VERSION 5.8 ;
BUSBITCHARS "[]" ;
DIVIDERCHAR "/" ;

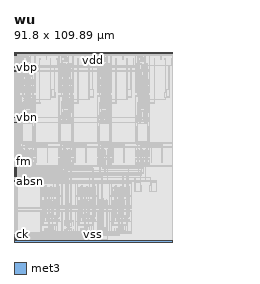
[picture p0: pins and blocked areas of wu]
MACRO wu
  CLASS BLOCK ;
  FOREIGN wu 0 0 ;
  ORIGIN 0 0 ;
  SIZE 91.800 BY 109.890 ;
  SYMMETRY X Y ;
  PIN absf
    DIRECTION OUTPUT ;
    USE SIGNAL ;
    PORT
      LAYER met3 ;
        RECT 0.000 41.260 1.400 41.600 ;
    END
  END absf
  PIN absn
    DIRECTION OUTPUT ;
    USE SIGNAL ;
    PORT
      LAYER met3 ;
        RECT 0.000 34.960 1.400 35.300 ;
    END
  END absn
  PIN ck
    DIRECTION INPUT ;
    USE SIGNAL ;
    PORT
      LAYER met3 ;
        RECT 0.000 3.930 1.400 4.270 ;
    END
  END ck
  PIN ck3
    DIRECTION INPUT ;
    USE SIGNAL ;
    PORT
      LAYER met3 ;
        RECT 0.000 3.230 1.400 3.570 ;
    END
  END ck3
  PIN fm
    DIRECTION INOUT ;
    USE SIGNAL ;
    PORT
      LAYER met3 ;
        RECT 0.000 41.960 1.400 42.300 ;
    END
  END fm
  PIN fp
    DIRECTION INOUT ;
    USE SIGNAL ;
    PORT
      LAYER met3 ;
        RECT 0.000 42.660 1.400 43.000 ;
    END
  END fp
  PIN lat
    DIRECTION INPUT ;
    USE SIGNAL ;
    PORT
      LAYER met3 ;
        RECT 0.000 2.530 1.400 2.870 ;
    END
  END lat
  PIN latb
    DIRECTION INPUT ;
    USE SIGNAL ;
    PORT
      LAYER met3 ;
        RECT 0.000 1.830 1.400 2.170 ;
    END
  END latb
  PIN lq
    DIRECTION INPUT ;
    USE SIGNAL ;
    PORT
      LAYER met3 ;
        RECT 0.000 1.130 1.400 1.470 ;
    END
  END lq
  PIN nm
    DIRECTION INOUT ;
    USE SIGNAL ;
    PORT
      LAYER met3 ;
        RECT 0.000 39.160 1.400 39.500 ;
    END
  END nm
  PIN np
    DIRECTION INOUT ;
    USE SIGNAL ;
    PORT
      LAYER met3 ;
        RECT 0.000 39.860 1.400 40.200 ;
    END
  END np
  PIN q1
    DIRECTION OUTPUT ;
    USE SIGNAL ;
    PORT
      LAYER met3 ;
        RECT 0.000 40.560 1.400 40.900 ;
    END
  END q1
  PIN q2
    DIRECTION OUTPUT ;
    USE SIGNAL ;
    PORT
      LAYER met3 ;
        RECT 0.000 38.460 1.400 38.800 ;
    END
  END q2
  PIN sen
    DIRECTION INPUT ;
    USE SIGNAL ;
    PORT
      LAYER met3 ;
        RECT 0.000 37.760 1.400 38.100 ;
    END
  END sen
  PIN vbn
    DIRECTION INPUT ;
    USE SIGNAL ;
    PORT
      LAYER met3 ;
        RECT 0.000 71.840 1.400 72.180 ;
    END
  END vbn
  PIN vbnc
    DIRECTION INPUT ;
    USE SIGNAL ;
    PORT
      LAYER met3 ;
        RECT 0.000 68.970 1.400 69.310 ;
    END
  END vbnc
  PIN vbp
    DIRECTION INPUT ;
    USE SIGNAL ;
    PORT
      LAYER met3 ;
        RECT 0.000 100.910 1.400 101.250 ;
    END
  END vbp
  PIN vbpc
    DIRECTION INPUT ;
    USE SIGNAL ;
    PORT
      LAYER met3 ;
        RECT 0.000 98.570 1.400 98.910 ;
    END
  END vbpc
  PIN vcm
    DIRECTION INOUT ;
    USE SIGNAL ;
    PORT
      LAYER met3 ;
        RECT 0.000 108.020 1.400 108.360 ;
    END
  END vcm
  PIN vdd
    DIRECTION INOUT ;
    USE POWER ;
    PORT
      LAYER met3 ;
        RECT 0.000 109.090 91.800 109.890 ;
    END
  END vdd
  PIN vss
    DIRECTION INOUT ;
    USE GROUND ;
    PORT
      LAYER met3 ;
        RECT 0.000 0.000 91.800 0.800 ;
    END
  END vss
  OBS
    LAYER li1 ;
      RECT 0.000 0.000 91.800 109.890 ;
    LAYER met1 ;
      RECT 40.800 6.920 41.030 9.690 ;
      RECT 37.415 9.690 45.960 10.030 ;
      RECT 45.960 6.920 46.190 10.030 ;
      RECT 45.810 10.210 46.150 10.550 ;
      RECT 46.045 12.230 46.275 14.400 ;
      RECT 46.045 14.400 46.745 14.740 ;
      RECT 41.155 12.230 41.385 15.340 ;
      RECT 41.385 15.000 47.345 15.340 ;
      RECT 15.350 5.350 15.690 5.790 ;
      RECT 27.410 5.350 28.090 5.790 ;
      RECT 35.840 5.350 36.520 5.790 ;
      RECT 48.240 5.350 48.920 5.790 ;
      RECT 55.440 5.350 56.120 5.790 ;
      RECT 29.270 6.130 29.500 7.220 ;
      RECT 31.850 6.130 32.080 7.220 ;
      RECT 34.430 6.130 34.660 7.220 ;
      RECT 17.740 6.130 17.970 7.920 ;
      RECT 38.570 6.130 38.800 7.920 ;
      RECT 53.325 6.130 53.555 7.920 ;
      RECT 58.170 6.130 58.400 7.920 ;
      RECT 15.350 6.130 15.690 11.700 ;
      RECT 35.840 6.130 36.520 11.700 ;
      RECT 55.440 6.130 56.120 11.700 ;
      RECT 21.115 12.040 21.345 13.230 ;
      RECT 22.845 12.040 23.075 13.230 ;
      RECT 24.425 12.040 24.655 13.230 ;
      RECT 26.005 12.040 26.235 13.230 ;
      RECT 41.945 12.040 42.175 13.230 ;
      RECT 43.675 12.040 43.905 13.230 ;
      RECT 45.255 12.040 45.485 13.230 ;
      RECT 46.835 12.040 47.065 13.230 ;
      RECT 61.545 12.040 61.775 13.230 ;
      RECT 63.275 12.040 63.505 13.230 ;
      RECT 64.855 12.040 65.085 13.230 ;
      RECT 66.435 12.040 66.665 13.230 ;
      RECT 15.350 12.040 15.690 17.670 ;
      RECT 27.410 6.130 28.090 17.670 ;
      RECT 15.350 11.700 27.410 12.040 ;
      RECT 35.840 12.040 36.520 17.670 ;
      RECT 48.240 6.130 48.920 17.670 ;
      RECT 35.840 11.700 48.240 12.040 ;
      RECT 55.440 12.040 56.120 17.670 ;
      RECT 55.440 11.700 67.840 12.040 ;
      RECT 0.300 17.670 67.840 18.170 ;
      RECT 67.840 5.350 68.180 18.170 ;
      RECT 0.300 4.850 68.180 5.350 ;
      RECT 15.350 5.790 67.840 6.130 ;
      RECT 44.315 21.090 44.545 24.460 ;
      RECT 45.255 21.090 45.485 24.460 ;
      RECT 39.215 24.460 46.835 24.800 ;
      RECT 46.835 21.090 47.065 24.800 ;
      RECT 44.785 27.000 45.015 29.170 ;
      RECT 44.785 29.170 46.365 29.510 ;
      RECT 46.365 27.000 46.595 29.510 ;
      RECT 43.995 27.000 44.225 29.770 ;
      RECT 43.995 29.770 47.155 30.110 ;
      RECT 47.155 27.000 47.385 30.110 ;
      RECT 37.375 27.000 37.605 31.310 ;
      RECT 37.605 30.970 47.345 31.310 ;
      RECT 15.350 20.120 15.690 20.560 ;
      RECT 27.410 20.120 28.090 20.560 ;
      RECT 35.840 20.120 36.520 20.560 ;
      RECT 48.240 20.120 48.920 20.560 ;
      RECT 55.440 20.120 56.120 20.560 ;
      RECT 20.175 20.900 20.405 22.090 ;
      RECT 22.695 20.900 22.925 22.090 ;
      RECT 31.850 20.900 32.080 22.090 ;
      RECT 41.005 20.900 41.235 22.090 ;
      RECT 43.525 20.900 43.755 22.090 ;
      RECT 60.605 20.900 60.835 22.090 ;
      RECT 63.125 20.900 63.355 22.090 ;
      RECT 17.655 20.900 17.885 23.090 ;
      RECT 25.215 20.900 25.445 23.090 ;
      RECT 38.485 20.900 38.715 23.090 ;
      RECT 46.045 20.900 46.275 23.090 ;
      RECT 58.085 20.900 58.315 23.090 ;
      RECT 65.645 20.900 65.875 23.090 ;
      RECT 53.325 20.900 53.555 23.690 ;
      RECT 15.350 20.900 15.690 26.470 ;
      RECT 35.840 20.900 36.520 26.470 ;
      RECT 55.440 20.900 56.120 26.470 ;
      RECT 17.335 26.810 17.565 29.000 ;
      RECT 20.645 26.810 20.875 29.000 ;
      RECT 24.745 26.810 24.975 29.000 ;
      RECT 38.165 26.810 38.395 29.000 ;
      RECT 41.475 26.810 41.705 29.000 ;
      RECT 45.575 26.810 45.805 29.000 ;
      RECT 57.765 26.810 57.995 29.000 ;
      RECT 61.075 26.810 61.305 29.000 ;
      RECT 65.175 26.810 65.405 29.000 ;
      RECT 15.350 26.810 15.690 33.690 ;
      RECT 27.410 20.900 28.090 33.690 ;
      RECT 15.350 26.470 27.410 26.810 ;
      RECT 35.840 26.810 36.520 33.690 ;
      RECT 48.240 20.900 48.920 33.690 ;
      RECT 35.840 26.470 48.240 26.810 ;
      RECT 55.440 26.810 56.120 33.690 ;
      RECT 1.500 33.690 67.840 34.190 ;
      RECT 67.840 20.120 68.180 34.190 ;
      RECT 1.500 19.620 68.180 20.120 ;
      RECT 15.350 20.560 67.840 20.900 ;
      RECT 55.440 26.470 67.840 26.810 ;
      RECT 3.810 44.080 4.150 47.640 ;
      RECT 25.910 44.080 26.250 47.640 ;
      RECT 48.010 44.080 48.350 47.640 ;
      RECT 70.110 44.080 70.450 47.640 ;
      RECT 3.810 47.640 11.900 48.140 ;
      RECT 11.900 44.080 12.240 48.140 ;
      RECT 25.910 47.640 34.000 48.140 ;
      RECT 34.000 44.080 34.340 48.140 ;
      RECT 48.010 47.640 56.100 48.140 ;
      RECT 56.100 44.080 56.440 48.140 ;
      RECT 70.110 47.640 78.200 48.140 ;
      RECT 78.200 44.080 78.540 48.140 ;
      RECT 0.300 43.580 91.800 44.080 ;
      RECT 3.810 50.090 4.150 54.650 ;
      RECT 11.900 49.590 12.240 54.650 ;
      RECT 3.810 49.590 11.900 50.090 ;
      RECT 25.910 50.090 26.250 54.650 ;
      RECT 34.000 49.590 34.340 54.650 ;
      RECT 25.910 49.590 34.000 50.090 ;
      RECT 48.010 50.090 48.350 54.650 ;
      RECT 56.100 49.590 56.440 54.650 ;
      RECT 48.010 49.590 56.100 50.090 ;
      RECT 70.110 50.090 70.450 54.650 ;
      RECT 1.500 54.650 91.800 55.150 ;
      RECT 78.200 50.090 78.540 54.650 ;
      RECT 70.110 49.590 78.540 50.090 ;
      RECT 3.810 57.530 4.150 59.940 ;
      RECT 25.910 57.530 26.250 59.940 ;
      RECT 48.010 57.530 48.350 59.940 ;
      RECT 70.110 57.530 70.450 59.940 ;
      RECT 5.540 60.280 5.770 61.220 ;
      RECT 6.330 60.280 6.560 61.220 ;
      RECT 7.910 60.280 8.140 61.220 ;
      RECT 9.490 60.280 9.720 61.220 ;
      RECT 10.280 60.280 10.510 61.220 ;
      RECT 27.640 60.280 27.870 61.220 ;
      RECT 28.430 60.280 28.660 61.220 ;
      RECT 30.010 60.280 30.240 61.220 ;
      RECT 31.590 60.280 31.820 61.220 ;
      RECT 32.380 60.280 32.610 61.220 ;
      RECT 49.740 60.280 49.970 61.220 ;
      RECT 50.530 60.280 50.760 61.220 ;
      RECT 52.110 60.280 52.340 61.220 ;
      RECT 53.690 60.280 53.920 61.220 ;
      RECT 54.480 60.280 54.710 61.220 ;
      RECT 71.840 60.280 72.070 61.220 ;
      RECT 72.630 60.280 72.860 61.220 ;
      RECT 74.210 60.280 74.440 61.220 ;
      RECT 75.790 60.280 76.020 61.220 ;
      RECT 76.580 60.280 76.810 61.220 ;
      RECT 3.810 60.280 4.150 62.750 ;
      RECT 25.910 60.280 26.250 62.750 ;
      RECT 48.010 60.280 48.350 62.750 ;
      RECT 70.110 60.280 70.450 62.750 ;
      RECT 5.540 63.090 5.770 64.030 ;
      RECT 6.330 63.090 6.560 64.030 ;
      RECT 7.910 63.090 8.140 64.030 ;
      RECT 9.490 63.090 9.720 64.030 ;
      RECT 10.280 63.090 10.510 64.030 ;
      RECT 27.640 63.090 27.870 64.030 ;
      RECT 28.430 63.090 28.660 64.030 ;
      RECT 30.010 63.090 30.240 64.030 ;
      RECT 31.590 63.090 31.820 64.030 ;
      RECT 32.380 63.090 32.610 64.030 ;
      RECT 49.740 63.090 49.970 64.030 ;
      RECT 50.530 63.090 50.760 64.030 ;
      RECT 52.110 63.090 52.340 64.030 ;
      RECT 53.690 63.090 53.920 64.030 ;
      RECT 54.480 63.090 54.710 64.030 ;
      RECT 71.840 63.090 72.070 64.030 ;
      RECT 72.630 63.090 72.860 64.030 ;
      RECT 74.210 63.090 74.440 64.030 ;
      RECT 75.790 63.090 76.020 64.030 ;
      RECT 76.580 63.090 76.810 64.030 ;
      RECT 3.810 63.090 4.150 69.720 ;
      RECT 25.910 63.090 26.250 69.720 ;
      RECT 48.010 63.090 48.350 69.720 ;
      RECT 70.110 63.090 70.450 69.720 ;
      RECT 4.685 70.060 4.915 71.150 ;
      RECT 7.265 70.060 7.495 71.150 ;
      RECT 9.845 70.060 10.075 71.150 ;
      RECT 26.785 70.060 27.015 71.150 ;
      RECT 29.365 70.060 29.595 71.150 ;
      RECT 31.945 70.060 32.175 71.150 ;
      RECT 48.885 70.060 49.115 71.150 ;
      RECT 51.465 70.060 51.695 71.150 ;
      RECT 54.045 70.060 54.275 71.150 ;
      RECT 70.985 70.060 71.215 71.150 ;
      RECT 73.565 70.060 73.795 71.150 ;
      RECT 76.145 70.060 76.375 71.150 ;
      RECT 5.860 73.020 6.090 74.710 ;
      RECT 3.810 70.060 4.150 73.020 ;
      RECT 7.440 72.680 7.670 74.710 ;
      RECT 4.150 72.680 7.440 73.020 ;
      RECT 27.960 73.020 28.190 74.710 ;
      RECT 25.910 70.060 26.250 73.020 ;
      RECT 29.540 72.680 29.770 74.710 ;
      RECT 26.250 72.680 29.540 73.020 ;
      RECT 50.060 73.020 50.290 74.710 ;
      RECT 48.010 70.060 48.350 73.020 ;
      RECT 51.640 72.680 51.870 74.710 ;
      RECT 48.350 72.680 51.640 73.020 ;
      RECT 72.160 73.020 72.390 74.710 ;
      RECT 70.110 70.060 70.450 73.020 ;
      RECT 73.740 72.680 73.970 74.710 ;
      RECT 70.450 72.680 73.740 73.020 ;
      RECT 3.810 73.020 4.150 84.240 ;
      RECT 25.910 73.020 26.250 84.240 ;
      RECT 48.010 73.020 48.350 84.240 ;
      RECT 70.110 73.020 70.450 84.240 ;
      RECT 3.810 59.940 11.900 60.280 ;
      RECT 3.810 62.750 11.900 63.090 ;
      RECT 3.810 84.240 12.240 84.740 ;
      RECT 11.900 57.530 12.240 84.240 ;
      RECT 3.810 69.720 11.900 70.060 ;
      RECT 25.910 59.940 34.000 60.280 ;
      RECT 25.910 62.750 34.000 63.090 ;
      RECT 25.910 84.240 34.340 84.740 ;
      RECT 34.000 57.530 34.340 84.240 ;
      RECT 25.910 69.720 34.000 70.060 ;
      RECT 48.010 59.940 56.100 60.280 ;
      RECT 48.010 62.750 56.100 63.090 ;
      RECT 48.010 84.240 56.440 84.740 ;
      RECT 56.100 57.530 56.440 84.240 ;
      RECT 48.010 69.720 56.100 70.060 ;
      RECT 70.110 84.240 78.540 84.740 ;
      RECT 78.200 57.530 78.540 84.240 ;
      RECT 0.300 57.030 91.800 57.530 ;
      RECT 70.110 59.940 78.200 60.280 ;
      RECT 70.110 62.750 78.200 63.090 ;
      RECT 70.110 69.720 78.200 70.060 ;
      RECT 3.810 86.690 4.150 87.130 ;
      RECT 25.910 86.690 26.250 87.130 ;
      RECT 48.010 86.690 48.350 87.130 ;
      RECT 70.110 86.690 70.450 87.130 ;
      RECT 4.640 87.470 4.870 89.660 ;
      RECT 5.730 87.470 5.960 89.660 ;
      RECT 7.910 87.470 8.140 89.660 ;
      RECT 10.090 87.470 10.320 89.660 ;
      RECT 11.180 87.470 11.410 89.660 ;
      RECT 26.740 87.470 26.970 89.660 ;
      RECT 27.830 87.470 28.060 89.660 ;
      RECT 30.010 87.470 30.240 89.660 ;
      RECT 32.190 87.470 32.420 89.660 ;
      RECT 33.280 87.470 33.510 89.660 ;
      RECT 48.840 87.470 49.070 89.660 ;
      RECT 49.930 87.470 50.160 89.660 ;
      RECT 52.110 87.470 52.340 89.660 ;
      RECT 54.290 87.470 54.520 89.660 ;
      RECT 55.380 87.470 55.610 89.660 ;
      RECT 70.940 87.470 71.170 89.660 ;
      RECT 72.030 87.470 72.260 89.660 ;
      RECT 74.210 87.470 74.440 89.660 ;
      RECT 76.390 87.470 76.620 89.660 ;
      RECT 77.480 87.470 77.710 89.660 ;
      RECT 3.810 87.470 4.150 91.190 ;
      RECT 25.910 87.470 26.250 91.190 ;
      RECT 48.010 87.470 48.350 91.190 ;
      RECT 70.110 87.470 70.450 91.190 ;
      RECT 4.640 91.530 4.870 93.720 ;
      RECT 5.730 91.530 5.960 93.720 ;
      RECT 7.910 91.530 8.140 93.720 ;
      RECT 10.090 91.530 10.320 93.720 ;
      RECT 11.180 91.530 11.410 93.720 ;
      RECT 26.740 91.530 26.970 93.720 ;
      RECT 27.830 91.530 28.060 93.720 ;
      RECT 30.010 91.530 30.240 93.720 ;
      RECT 32.190 91.530 32.420 93.720 ;
      RECT 33.280 91.530 33.510 93.720 ;
      RECT 48.840 91.530 49.070 93.720 ;
      RECT 49.930 91.530 50.160 93.720 ;
      RECT 52.110 91.530 52.340 93.720 ;
      RECT 54.290 91.530 54.520 93.720 ;
      RECT 55.380 91.530 55.610 93.720 ;
      RECT 70.940 91.530 71.170 93.720 ;
      RECT 72.030 91.530 72.260 93.720 ;
      RECT 74.210 91.530 74.440 93.720 ;
      RECT 76.390 91.530 76.620 93.720 ;
      RECT 77.480 91.530 77.710 93.720 ;
      RECT 3.810 91.530 4.150 99.410 ;
      RECT 25.910 91.530 26.250 99.410 ;
      RECT 48.010 91.530 48.350 99.410 ;
      RECT 70.110 91.530 70.450 99.410 ;
      RECT 6.105 99.750 6.335 101.940 ;
      RECT 28.205 99.750 28.435 101.940 ;
      RECT 50.305 99.750 50.535 101.940 ;
      RECT 72.405 99.750 72.635 101.940 ;
      RECT 8.135 99.750 8.365 102.440 ;
      RECT 9.715 99.750 9.945 102.440 ;
      RECT 30.235 99.750 30.465 102.440 ;
      RECT 31.815 99.750 32.045 102.440 ;
      RECT 52.335 99.750 52.565 102.440 ;
      RECT 53.915 99.750 54.145 102.440 ;
      RECT 74.435 99.750 74.665 102.440 ;
      RECT 76.015 99.750 76.245 102.440 ;
      RECT 3.810 99.750 4.150 108.150 ;
      RECT 3.810 99.410 11.900 99.750 ;
      RECT 3.810 87.130 11.900 87.470 ;
      RECT 3.810 91.190 11.900 91.530 ;
      RECT 11.900 86.690 12.240 108.150 ;
      RECT 3.810 86.190 12.240 86.690 ;
      RECT 25.910 99.750 26.250 108.150 ;
      RECT 25.910 99.410 34.000 99.750 ;
      RECT 25.910 87.130 34.000 87.470 ;
      RECT 25.910 91.190 34.000 91.530 ;
      RECT 34.000 86.690 34.340 108.150 ;
      RECT 25.910 86.190 34.340 86.690 ;
      RECT 48.010 99.750 48.350 108.150 ;
      RECT 48.010 99.410 56.100 99.750 ;
      RECT 48.010 87.130 56.100 87.470 ;
      RECT 48.010 91.190 56.100 91.530 ;
      RECT 56.100 86.690 56.440 108.150 ;
      RECT 48.010 86.190 56.440 86.690 ;
      RECT 70.110 99.750 70.450 108.150 ;
      RECT 70.110 99.410 78.200 99.750 ;
      RECT 1.500 108.150 91.800 108.650 ;
      RECT 78.200 86.690 78.540 108.150 ;
      RECT 70.110 86.190 78.540 86.690 ;
      RECT 70.110 87.130 78.200 87.470 ;
      RECT 70.110 91.190 78.200 91.530 ;
      RECT 76.255 82.780 76.595 83.120 ;
      RECT 72.055 83.340 72.395 83.680 ;
      RECT 73.120 87.660 73.350 89.830 ;
      RECT 73.120 89.830 74.190 90.170 ;
      RECT 74.460 89.830 75.530 90.170 ;
      RECT 75.300 87.660 75.530 89.830 ;
      RECT 70.855 90.350 71.195 90.690 ;
      RECT 73.120 91.720 73.350 93.890 ;
      RECT 73.120 93.890 74.790 94.230 ;
      RECT 73.860 94.490 75.530 94.830 ;
      RECT 75.300 91.720 75.530 94.490 ;
      RECT 70.855 95.010 71.195 95.350 ;
      RECT 72.160 96.190 72.390 97.880 ;
      RECT 73.740 96.190 73.970 97.880 ;
      RECT 72.160 95.850 74.190 96.190 ;
      RECT 74.680 96.190 74.910 97.880 ;
      RECT 76.260 95.850 76.490 97.880 ;
      RECT 74.460 95.850 76.260 96.190 ;
      RECT 72.660 98.050 73.180 98.390 ;
      RECT 72.950 96.380 73.180 98.050 ;
      RECT 75.470 96.380 75.700 98.050 ;
      RECT 75.470 98.050 75.990 98.390 ;
      RECT 77.455 98.570 77.795 98.910 ;
      RECT 72.060 102.610 73.725 102.950 ;
      RECT 73.495 99.940 73.725 102.610 ;
      RECT 75.225 99.940 75.455 102.610 ;
      RECT 75.225 102.610 77.190 102.950 ;
      RECT 70.855 103.130 71.195 103.470 ;
      RECT 72.055 103.690 72.395 104.030 ;
      RECT 69.055 105.345 69.395 105.995 ;
      RECT 81.005 105.345 81.345 105.995 ;
      RECT 84.855 105.345 85.195 105.995 ;
      RECT 87.305 105.345 87.645 105.995 ;
      RECT 91.155 105.345 91.495 105.995 ;
      RECT 73.420 104.870 73.650 106.560 ;
      RECT 75.000 104.530 75.230 106.560 ;
      RECT 72.060 104.530 75.000 104.870 ;
      RECT 71.460 106.730 74.210 107.070 ;
      RECT 74.210 105.060 74.440 107.070 ;
      RECT 75.655 107.250 75.995 107.590 ;
      RECT 51.760 94.490 53.430 94.830 ;
      RECT 53.200 91.720 53.430 94.490 ;
      RECT 49.960 102.610 51.625 102.950 ;
      RECT 51.395 99.940 51.625 102.610 ;
      RECT 53.125 99.940 53.355 102.610 ;
      RECT 53.125 102.610 55.090 102.950 ;
      RECT 49.955 83.340 50.295 83.680 ;
      RECT 48.755 95.010 49.095 95.350 ;
      RECT 48.755 103.130 49.095 103.470 ;
      RECT 54.155 82.780 54.495 83.120 ;
      RECT 49.955 103.690 50.295 104.030 ;
      RECT 50.060 96.190 50.290 97.880 ;
      RECT 51.640 96.190 51.870 97.880 ;
      RECT 50.060 95.850 52.090 96.190 ;
      RECT 46.955 105.345 47.295 105.995 ;
      RECT 58.905 105.345 59.245 105.995 ;
      RECT 62.755 105.345 63.095 105.995 ;
      RECT 65.205 105.345 65.545 105.995 ;
      RECT 52.580 96.190 52.810 97.880 ;
      RECT 54.160 95.850 54.390 97.880 ;
      RECT 52.360 95.850 54.160 96.190 ;
      RECT 48.755 90.350 49.095 90.690 ;
      RECT 51.020 87.660 51.250 89.830 ;
      RECT 51.020 89.830 52.090 90.170 ;
      RECT 50.560 98.050 51.080 98.390 ;
      RECT 50.850 96.380 51.080 98.050 ;
      RECT 53.370 96.380 53.600 98.050 ;
      RECT 53.370 98.050 53.890 98.390 ;
      RECT 51.320 104.870 51.550 106.560 ;
      RECT 52.900 104.530 53.130 106.560 ;
      RECT 49.960 104.530 52.900 104.870 ;
      RECT 51.020 91.720 51.250 93.890 ;
      RECT 51.020 93.890 52.690 94.230 ;
      RECT 49.360 106.730 52.110 107.070 ;
      RECT 52.110 105.060 52.340 107.070 ;
      RECT 52.360 89.830 53.430 90.170 ;
      RECT 53.200 87.660 53.430 89.830 ;
      RECT 53.555 107.250 53.895 107.590 ;
      RECT 55.355 98.570 55.695 98.910 ;
      RECT 52.360 78.850 53.130 79.190 ;
      RECT 52.900 77.930 53.130 78.850 ;
      RECT 49.955 79.370 50.295 79.710 ;
      RECT 54.155 79.370 54.495 79.710 ;
      RECT 49.740 80.550 49.970 81.490 ;
      RECT 50.530 80.550 50.760 81.490 ;
      RECT 52.110 80.550 52.340 81.490 ;
      RECT 53.690 80.550 53.920 81.490 ;
      RECT 54.480 80.210 54.710 81.490 ;
      RECT 49.360 80.210 54.480 80.550 ;
      RECT 51.320 80.740 51.550 82.000 ;
      RECT 51.550 81.660 52.690 82.000 ;
      RECT 51.760 82.260 52.900 82.600 ;
      RECT 52.900 80.740 53.130 82.600 ;
      RECT 51.320 60.470 51.550 61.390 ;
      RECT 51.320 61.390 52.090 61.730 ;
      RECT 52.360 61.390 53.130 61.730 ;
      RECT 52.900 60.470 53.130 61.390 ;
      RECT 50.555 61.910 50.895 62.250 ;
      RECT 51.320 63.280 51.550 64.540 ;
      RECT 51.550 64.200 52.690 64.540 ;
      RECT 49.360 58.545 51.835 58.885 ;
      RECT 51.760 64.800 52.900 65.140 ;
      RECT 52.900 63.280 53.130 65.140 ;
      RECT 50.555 65.320 50.895 65.660 ;
      RECT 50.060 66.500 50.290 68.190 ;
      RECT 51.640 66.500 51.870 68.190 ;
      RECT 50.060 66.160 52.090 66.500 ;
      RECT 52.580 66.500 52.810 68.190 ;
      RECT 54.160 66.160 54.390 68.190 ;
      RECT 52.360 66.160 54.160 66.500 ;
      RECT 50.560 68.360 51.080 68.700 ;
      RECT 50.850 66.690 51.080 68.360 ;
      RECT 53.370 66.690 53.600 68.360 ;
      RECT 53.370 68.360 53.890 68.700 ;
      RECT 48.755 68.880 49.095 69.220 ;
      RECT 50.175 70.250 50.405 71.320 ;
      RECT 49.360 71.320 52.755 71.660 ;
      RECT 52.755 70.250 52.985 71.660 ;
      RECT 54.160 71.320 55.335 71.660 ;
      RECT 55.335 70.250 55.565 71.660 ;
      RECT 55.355 71.840 55.695 72.180 ;
      RECT 52.580 73.020 52.810 74.710 ;
      RECT 54.160 73.020 54.390 74.710 ;
      RECT 52.580 72.680 54.490 73.020 ;
      RECT 53.370 73.210 53.600 75.220 ;
      RECT 53.600 74.880 55.690 75.220 ;
      RECT 50.850 73.210 51.080 75.820 ;
      RECT 51.080 75.480 55.090 75.820 ;
      RECT 54.155 76.000 54.495 76.340 ;
      RECT 53.555 76.560 53.895 76.900 ;
      RECT 49.740 77.740 49.970 78.680 ;
      RECT 50.530 77.740 50.760 78.680 ;
      RECT 52.110 77.740 52.340 78.680 ;
      RECT 53.690 77.740 53.920 78.680 ;
      RECT 54.480 77.400 54.710 78.680 ;
      RECT 49.360 77.400 54.480 77.740 ;
      RECT 51.320 77.930 51.550 78.850 ;
      RECT 51.320 78.850 52.090 79.190 ;
      RECT 52.615 58.545 55.090 58.885 ;
      RECT 76.255 79.370 76.595 79.710 ;
      RECT 73.860 64.800 75.000 65.140 ;
      RECT 75.000 63.280 75.230 65.140 ;
      RECT 71.840 80.550 72.070 81.490 ;
      RECT 72.630 80.550 72.860 81.490 ;
      RECT 74.210 80.550 74.440 81.490 ;
      RECT 75.790 80.550 76.020 81.490 ;
      RECT 76.580 80.210 76.810 81.490 ;
      RECT 71.460 80.210 76.580 80.550 ;
      RECT 74.460 61.390 75.230 61.730 ;
      RECT 75.000 60.470 75.230 61.390 ;
      RECT 73.420 80.740 73.650 82.000 ;
      RECT 73.650 81.660 74.790 82.000 ;
      RECT 72.275 70.250 72.505 71.320 ;
      RECT 71.460 71.320 74.855 71.660 ;
      RECT 74.855 70.250 75.085 71.660 ;
      RECT 73.860 82.260 75.000 82.600 ;
      RECT 75.000 80.740 75.230 82.600 ;
      RECT 76.260 71.320 77.435 71.660 ;
      RECT 77.435 70.250 77.665 71.660 ;
      RECT 72.655 65.320 72.995 65.660 ;
      RECT 77.455 71.840 77.795 72.180 ;
      RECT 71.460 58.545 73.935 58.885 ;
      RECT 74.680 73.020 74.910 74.710 ;
      RECT 76.260 73.020 76.490 74.710 ;
      RECT 74.680 72.680 76.590 73.020 ;
      RECT 72.655 61.910 72.995 62.250 ;
      RECT 75.470 73.210 75.700 75.220 ;
      RECT 75.700 74.880 77.790 75.220 ;
      RECT 72.160 66.500 72.390 68.190 ;
      RECT 73.740 66.500 73.970 68.190 ;
      RECT 72.160 66.160 74.190 66.500 ;
      RECT 72.950 73.210 73.180 75.820 ;
      RECT 73.180 75.480 77.190 75.820 ;
      RECT 74.680 66.500 74.910 68.190 ;
      RECT 76.260 66.160 76.490 68.190 ;
      RECT 74.460 66.160 76.260 66.500 ;
      RECT 76.255 76.000 76.595 76.340 ;
      RECT 74.715 58.545 77.190 58.885 ;
      RECT 75.655 76.560 75.995 76.900 ;
      RECT 73.420 63.280 73.650 64.540 ;
      RECT 73.650 64.200 74.790 64.540 ;
      RECT 71.840 77.740 72.070 78.680 ;
      RECT 72.630 77.740 72.860 78.680 ;
      RECT 74.210 77.740 74.440 78.680 ;
      RECT 75.790 77.740 76.020 78.680 ;
      RECT 76.580 77.400 76.810 78.680 ;
      RECT 71.460 77.400 76.580 77.740 ;
      RECT 72.660 68.360 73.180 68.700 ;
      RECT 72.950 66.690 73.180 68.360 ;
      RECT 75.470 66.690 75.700 68.360 ;
      RECT 75.470 68.360 75.990 68.700 ;
      RECT 73.420 77.930 73.650 78.850 ;
      RECT 73.420 78.850 74.190 79.190 ;
      RECT 74.460 78.850 75.230 79.190 ;
      RECT 75.000 77.930 75.230 78.850 ;
      RECT 73.420 60.470 73.650 61.390 ;
      RECT 73.420 61.390 74.190 61.730 ;
      RECT 70.855 68.880 71.195 69.220 ;
      RECT 72.055 79.370 72.395 79.710 ;
      RECT 32.055 82.780 32.395 83.120 ;
      RECT 27.855 83.340 28.195 83.680 ;
      RECT 28.920 87.660 29.150 89.830 ;
      RECT 28.920 89.830 29.990 90.170 ;
      RECT 30.260 89.830 31.330 90.170 ;
      RECT 31.100 87.660 31.330 89.830 ;
      RECT 26.655 90.350 26.995 90.690 ;
      RECT 28.920 91.720 29.150 93.890 ;
      RECT 28.920 93.890 30.590 94.230 ;
      RECT 29.660 94.490 31.330 94.830 ;
      RECT 31.100 91.720 31.330 94.490 ;
      RECT 26.655 95.010 26.995 95.350 ;
      RECT 27.960 96.190 28.190 97.880 ;
      RECT 29.540 96.190 29.770 97.880 ;
      RECT 27.960 95.850 29.990 96.190 ;
      RECT 30.480 96.190 30.710 97.880 ;
      RECT 32.060 95.850 32.290 97.880 ;
      RECT 30.260 95.850 32.060 96.190 ;
      RECT 28.460 98.050 28.980 98.390 ;
      RECT 28.750 96.380 28.980 98.050 ;
      RECT 31.270 96.380 31.500 98.050 ;
      RECT 31.270 98.050 31.790 98.390 ;
      RECT 33.255 98.570 33.595 98.910 ;
      RECT 27.860 102.610 29.525 102.950 ;
      RECT 29.295 99.940 29.525 102.610 ;
      RECT 31.025 99.940 31.255 102.610 ;
      RECT 31.025 102.610 32.990 102.950 ;
      RECT 26.655 103.130 26.995 103.470 ;
      RECT 27.855 103.690 28.195 104.030 ;
      RECT 24.855 105.345 25.195 105.995 ;
      RECT 36.805 105.345 37.145 105.995 ;
      RECT 40.655 105.345 40.995 105.995 ;
      RECT 43.105 105.345 43.445 105.995 ;
      RECT 29.220 104.870 29.450 106.560 ;
      RECT 30.800 104.530 31.030 106.560 ;
      RECT 27.860 104.530 30.800 104.870 ;
      RECT 27.260 106.730 30.010 107.070 ;
      RECT 30.010 105.060 30.240 107.070 ;
      RECT 31.455 107.250 31.795 107.590 ;
      RECT 11.155 98.570 11.495 98.910 ;
      RECT 7.560 94.490 9.230 94.830 ;
      RECT 9.000 91.720 9.230 94.490 ;
      RECT 5.760 102.610 7.425 102.950 ;
      RECT 7.195 99.940 7.425 102.610 ;
      RECT 8.925 99.940 9.155 102.610 ;
      RECT 8.925 102.610 10.890 102.950 ;
      RECT 5.755 83.340 6.095 83.680 ;
      RECT 4.555 95.010 4.895 95.350 ;
      RECT 4.555 103.130 4.895 103.470 ;
      RECT 9.955 82.780 10.295 83.120 ;
      RECT 5.755 103.690 6.095 104.030 ;
      RECT 5.860 96.190 6.090 97.880 ;
      RECT 7.440 96.190 7.670 97.880 ;
      RECT 5.860 95.850 7.890 96.190 ;
      RECT 14.705 105.345 15.045 105.995 ;
      RECT 18.555 105.345 18.895 105.995 ;
      RECT 21.005 105.345 21.345 105.995 ;
      RECT 8.380 96.190 8.610 97.880 ;
      RECT 9.960 95.850 10.190 97.880 ;
      RECT 8.160 95.850 9.960 96.190 ;
      RECT 4.555 90.350 4.895 90.690 ;
      RECT 6.820 87.660 7.050 89.830 ;
      RECT 6.820 89.830 7.890 90.170 ;
      RECT 6.360 98.050 6.880 98.390 ;
      RECT 6.650 96.380 6.880 98.050 ;
      RECT 7.120 104.870 7.350 106.560 ;
      RECT 8.700 104.530 8.930 106.560 ;
      RECT 5.760 104.530 8.700 104.870 ;
      RECT 9.170 96.380 9.400 98.050 ;
      RECT 9.170 98.050 9.690 98.390 ;
      RECT 5.160 106.730 7.910 107.070 ;
      RECT 7.910 105.060 8.140 107.070 ;
      RECT 6.820 91.720 7.050 93.890 ;
      RECT 6.820 93.890 8.490 94.230 ;
      RECT 9.355 107.250 9.695 107.590 ;
      RECT 8.160 89.830 9.230 90.170 ;
      RECT 9.000 87.660 9.230 89.830 ;
      RECT 9.170 73.210 9.400 75.220 ;
      RECT 9.400 74.880 11.490 75.220 ;
      RECT 7.120 77.930 7.350 78.850 ;
      RECT 7.120 78.850 7.890 79.190 ;
      RECT 6.355 65.320 6.695 65.660 ;
      RECT 9.955 76.000 10.295 76.340 ;
      RECT 8.160 78.850 8.930 79.190 ;
      RECT 8.700 77.930 8.930 78.850 ;
      RECT 7.120 60.470 7.350 61.390 ;
      RECT 7.120 61.390 7.890 61.730 ;
      RECT 8.415 58.545 10.890 58.885 ;
      RECT 7.120 63.280 7.350 64.540 ;
      RECT 7.350 64.200 8.490 64.540 ;
      RECT 7.560 82.260 8.700 82.600 ;
      RECT 8.700 80.740 8.930 82.600 ;
      RECT 8.380 73.020 8.610 74.710 ;
      RECT 9.960 73.020 10.190 74.710 ;
      RECT 8.380 72.680 10.290 73.020 ;
      RECT 6.650 73.210 6.880 75.820 ;
      RECT 6.880 75.480 10.890 75.820 ;
      RECT 8.160 61.390 8.930 61.730 ;
      RECT 8.700 60.470 8.930 61.390 ;
      RECT 9.355 76.560 9.695 76.900 ;
      RECT 6.360 68.360 6.880 68.700 ;
      RECT 6.650 66.690 6.880 68.360 ;
      RECT 5.860 66.500 6.090 68.190 ;
      RECT 7.440 66.500 7.670 68.190 ;
      RECT 5.860 66.160 7.890 66.500 ;
      RECT 5.755 79.370 6.095 79.710 ;
      RECT 9.955 79.370 10.295 79.710 ;
      RECT 4.555 68.880 4.895 69.220 ;
      RECT 11.155 71.840 11.495 72.180 ;
      RECT 9.170 66.690 9.400 68.360 ;
      RECT 9.170 68.360 9.690 68.700 ;
      RECT 7.560 64.800 8.700 65.140 ;
      RECT 8.700 63.280 8.930 65.140 ;
      RECT 5.540 77.740 5.770 78.680 ;
      RECT 6.330 77.740 6.560 78.680 ;
      RECT 7.910 77.740 8.140 78.680 ;
      RECT 9.490 77.740 9.720 78.680 ;
      RECT 10.280 77.400 10.510 78.680 ;
      RECT 5.160 77.400 10.280 77.740 ;
      RECT 6.355 61.910 6.695 62.250 ;
      RECT 5.540 80.550 5.770 81.490 ;
      RECT 6.330 80.550 6.560 81.490 ;
      RECT 7.910 80.550 8.140 81.490 ;
      RECT 9.490 80.550 9.720 81.490 ;
      RECT 10.280 80.210 10.510 81.490 ;
      RECT 5.160 80.210 10.280 80.550 ;
      RECT 5.160 58.545 7.635 58.885 ;
      RECT 8.380 66.500 8.610 68.190 ;
      RECT 9.960 66.160 10.190 68.190 ;
      RECT 8.160 66.160 9.960 66.500 ;
      RECT 5.975 70.250 6.205 71.320 ;
      RECT 5.160 71.320 8.555 71.660 ;
      RECT 8.555 70.250 8.785 71.660 ;
      RECT 9.960 71.320 11.135 71.660 ;
      RECT 11.135 70.250 11.365 71.660 ;
      RECT 7.120 80.740 7.350 82.000 ;
      RECT 7.350 81.660 8.490 82.000 ;
      RECT 28.455 65.320 28.795 65.660 ;
      RECT 32.060 71.320 33.235 71.660 ;
      RECT 33.235 70.250 33.465 71.660 ;
      RECT 29.220 80.740 29.450 82.000 ;
      RECT 29.450 81.660 30.590 82.000 ;
      RECT 30.515 58.545 32.990 58.885 ;
      RECT 31.270 73.210 31.500 75.220 ;
      RECT 31.500 74.880 33.590 75.220 ;
      RECT 28.455 61.910 28.795 62.250 ;
      RECT 27.960 66.500 28.190 68.190 ;
      RECT 29.540 66.500 29.770 68.190 ;
      RECT 27.960 66.160 29.990 66.500 ;
      RECT 29.220 63.280 29.450 64.540 ;
      RECT 29.450 64.200 30.590 64.540 ;
      RECT 29.220 60.470 29.450 61.390 ;
      RECT 29.220 61.390 29.990 61.730 ;
      RECT 30.260 61.390 31.030 61.730 ;
      RECT 30.800 60.470 31.030 61.390 ;
      RECT 32.055 76.000 32.395 76.340 ;
      RECT 29.660 82.260 30.800 82.600 ;
      RECT 30.800 80.740 31.030 82.600 ;
      RECT 27.855 79.370 28.195 79.710 ;
      RECT 32.055 79.370 32.395 79.710 ;
      RECT 27.640 77.740 27.870 78.680 ;
      RECT 28.430 77.740 28.660 78.680 ;
      RECT 30.010 77.740 30.240 78.680 ;
      RECT 31.590 77.740 31.820 78.680 ;
      RECT 32.380 77.400 32.610 78.680 ;
      RECT 27.260 77.400 32.380 77.740 ;
      RECT 26.655 68.880 26.995 69.220 ;
      RECT 28.460 68.360 28.980 68.700 ;
      RECT 28.750 66.690 28.980 68.360 ;
      RECT 31.270 66.690 31.500 68.360 ;
      RECT 31.270 68.360 31.790 68.700 ;
      RECT 30.480 73.020 30.710 74.710 ;
      RECT 32.060 73.020 32.290 74.710 ;
      RECT 30.480 72.680 32.390 73.020 ;
      RECT 29.660 64.800 30.800 65.140 ;
      RECT 30.800 63.280 31.030 65.140 ;
      RECT 30.480 66.500 30.710 68.190 ;
      RECT 32.060 66.160 32.290 68.190 ;
      RECT 30.260 66.160 32.060 66.500 ;
      RECT 33.255 71.840 33.595 72.180 ;
      RECT 27.260 58.545 29.735 58.885 ;
      RECT 27.640 80.550 27.870 81.490 ;
      RECT 28.430 80.550 28.660 81.490 ;
      RECT 30.010 80.550 30.240 81.490 ;
      RECT 31.590 80.550 31.820 81.490 ;
      RECT 32.380 80.210 32.610 81.490 ;
      RECT 27.260 80.210 32.380 80.550 ;
      RECT 29.220 77.930 29.450 78.850 ;
      RECT 29.220 78.850 29.990 79.190 ;
      RECT 28.075 70.250 28.305 71.320 ;
      RECT 27.260 71.320 30.655 71.660 ;
      RECT 30.655 70.250 30.885 71.660 ;
      RECT 28.750 73.210 28.980 75.820 ;
      RECT 28.980 75.480 32.990 75.820 ;
      RECT 30.260 78.850 31.030 79.190 ;
      RECT 30.800 77.930 31.030 78.850 ;
      RECT 31.455 76.560 31.795 76.900 ;
      RECT 22.585 14.400 23.865 14.740 ;
      RECT 23.635 12.230 23.865 14.400 ;
      RECT 19.030 6.730 19.260 7.920 ;
      RECT 21.260 6.730 21.490 8.920 ;
      RECT 23.840 6.390 24.070 8.920 ;
      RECT 19.030 6.390 23.840 6.730 ;
      RECT 20.325 12.230 20.555 15.340 ;
      RECT 20.555 15.000 26.515 15.340 ;
      RECT 23.485 21.090 23.715 24.460 ;
      RECT 24.425 21.090 24.655 24.460 ;
      RECT 18.385 24.460 26.005 24.800 ;
      RECT 26.005 21.090 26.235 24.800 ;
      RECT 19.970 6.920 20.200 9.690 ;
      RECT 16.585 9.690 25.130 10.030 ;
      RECT 25.130 6.920 25.360 10.030 ;
      RECT 23.165 27.000 23.395 29.770 ;
      RECT 23.165 29.770 26.325 30.110 ;
      RECT 26.325 27.000 26.555 30.110 ;
      RECT 16.545 27.000 16.775 31.310 ;
      RECT 16.775 30.970 26.515 31.310 ;
      RECT 29.355 53.750 29.695 54.090 ;
      RECT 31.760 53.230 32.760 53.570 ;
      RECT 32.530 51.060 32.760 53.230 ;
      RECT 26.180 31.490 26.520 31.830 ;
      RECT 38.610 31.490 38.950 31.830 ;
      RECT 42.210 31.490 42.550 31.830 ;
      RECT 25.580 32.140 25.920 32.480 ;
      RECT 39.210 32.140 39.550 32.480 ;
      RECT 43.410 32.790 43.750 33.130 ;
      RECT 26.700 44.860 26.930 46.050 ;
      RECT 28.280 44.520 28.510 46.050 ;
      RECT 26.700 44.520 28.280 44.860 ;
      RECT 29.220 44.860 29.450 46.050 ;
      RECT 30.800 44.520 31.030 46.050 ;
      RECT 29.220 44.520 30.800 44.860 ;
      RECT 31.740 44.860 31.970 46.050 ;
      RECT 33.320 44.520 33.550 46.050 ;
      RECT 31.740 44.520 33.320 44.860 ;
      RECT 35.055 45.715 35.395 46.365 ;
      RECT 41.355 45.715 41.695 46.365 ;
      RECT 26.960 46.220 27.720 46.560 ;
      RECT 27.490 45.050 27.720 46.220 ;
      RECT 28.760 46.220 30.010 46.560 ;
      RECT 30.010 45.050 30.240 46.560 ;
      RECT 31.760 46.220 32.760 46.560 ;
      RECT 32.530 45.050 32.760 46.220 ;
      RECT 29.955 46.740 30.295 47.080 ;
      RECT 26.700 50.870 26.930 53.060 ;
      RECT 28.280 50.530 28.510 53.060 ;
      RECT 26.700 50.530 28.280 50.870 ;
      RECT 29.220 50.870 29.450 53.060 ;
      RECT 30.800 50.530 31.030 53.060 ;
      RECT 29.220 50.530 30.800 50.870 ;
      RECT 31.740 50.870 31.970 53.060 ;
      RECT 33.320 50.530 33.550 53.060 ;
      RECT 31.740 50.530 33.320 50.870 ;
      RECT 26.960 53.230 27.720 53.570 ;
      RECT 27.490 51.060 27.720 53.230 ;
      RECT 28.760 53.230 30.240 53.570 ;
      RECT 30.010 51.060 30.240 53.230 ;
      RECT 21.380 31.490 21.720 31.830 ;
      RECT 4.860 46.220 5.620 46.560 ;
      RECT 5.390 45.050 5.620 46.220 ;
      RECT 6.660 46.220 7.910 46.560 ;
      RECT 7.910 45.050 8.140 46.560 ;
      RECT 9.660 46.220 10.660 46.560 ;
      RECT 10.430 45.050 10.660 46.220 ;
      RECT 4.600 44.860 4.830 46.050 ;
      RECT 6.180 44.520 6.410 46.050 ;
      RECT 4.600 44.520 6.180 44.860 ;
      RECT 7.120 44.860 7.350 46.050 ;
      RECT 8.700 44.520 8.930 46.050 ;
      RECT 7.120 44.520 8.700 44.860 ;
      RECT 9.640 44.860 9.870 46.050 ;
      RECT 11.220 44.520 11.450 46.050 ;
      RECT 9.640 44.520 11.220 44.860 ;
      RECT 7.855 46.740 8.195 47.080 ;
      RECT 18.380 32.140 18.720 32.480 ;
      RECT 4.600 50.870 4.830 53.060 ;
      RECT 6.180 50.530 6.410 53.060 ;
      RECT 4.600 50.530 6.180 50.870 ;
      RECT 7.120 50.870 7.350 53.060 ;
      RECT 8.700 50.530 8.930 53.060 ;
      RECT 7.120 50.530 8.700 50.870 ;
      RECT 9.640 50.870 9.870 53.060 ;
      RECT 11.220 50.530 11.450 53.060 ;
      RECT 9.640 50.530 11.220 50.870 ;
      RECT 7.255 53.750 7.595 54.090 ;
      RECT 17.780 31.490 18.120 31.830 ;
      RECT 12.955 45.715 13.295 46.365 ;
      RECT 4.860 53.230 5.620 53.570 ;
      RECT 5.390 51.060 5.620 53.230 ;
      RECT 6.660 53.230 8.140 53.570 ;
      RECT 7.910 51.060 8.140 53.230 ;
      RECT 9.660 53.230 10.660 53.570 ;
      RECT 10.430 51.060 10.660 53.230 ;
      RECT 19.255 45.715 19.595 46.365 ;
      RECT 22.580 32.790 22.920 33.130 ;
      RECT 20.180 10.210 20.520 10.550 ;
      RECT 19.385 12.230 19.615 15.940 ;
      RECT 19.615 15.600 22.315 15.940 ;
      RECT 17.780 16.120 18.120 16.460 ;
      RECT 21.380 16.120 21.720 16.460 ;
      RECT 18.380 16.770 18.720 17.110 ;
      RECT 22.580 16.770 22.920 17.110 ;
      RECT 21.985 9.090 22.780 9.430 ;
      RECT 22.550 6.920 22.780 9.090 ;
      RECT 16.865 21.090 17.095 23.260 ;
      RECT 18.445 21.090 18.675 23.260 ;
      RECT 16.865 23.260 19.385 23.600 ;
      RECT 19.385 21.090 19.615 23.600 ;
      RECT 21.905 21.090 22.135 23.260 ;
      RECT 21.905 23.260 22.315 23.600 ;
      RECT 16.585 23.860 20.965 24.200 ;
      RECT 20.965 21.090 21.195 24.200 ;
      RECT 21.385 14.400 22.135 14.740 ;
      RECT 21.905 12.230 22.135 14.400 ;
      RECT 17.780 24.980 18.120 25.320 ;
      RECT 18.380 25.630 18.720 25.970 ;
      RECT 20.180 25.630 20.520 25.970 ;
      RECT 19.855 27.000 20.085 29.170 ;
      RECT 19.855 29.170 21.435 29.510 ;
      RECT 21.435 27.000 21.665 29.510 ;
      RECT 16.585 14.400 17.095 14.740 ;
      RECT 16.865 12.230 17.095 14.400 ;
      RECT 19.065 27.000 19.295 29.770 ;
      RECT 19.065 29.770 22.915 30.110 ;
      RECT 22.225 27.000 22.455 29.770 ;
      RECT 17.655 12.230 17.885 14.400 ;
      RECT 17.655 14.400 18.115 14.740 ;
      RECT 18.125 27.000 18.355 30.710 ;
      RECT 18.355 30.370 21.715 30.710 ;
      RECT 18.385 14.400 18.825 14.740 ;
      RECT 18.595 12.230 18.825 14.400 ;
      RECT 42.210 16.120 42.550 16.460 ;
      RECT 45.210 10.860 45.550 11.200 ;
      RECT 30.560 9.090 30.790 11.280 ;
      RECT 33.140 8.750 33.370 11.280 ;
      RECT 30.560 8.750 33.140 9.090 ;
      RECT 26.180 16.770 26.520 17.110 ;
      RECT 39.210 16.770 39.550 17.110 ;
      RECT 43.410 16.770 43.750 17.110 ;
      RECT 31.850 9.280 32.080 11.450 ;
      RECT 31.850 11.450 32.730 11.790 ;
      RECT 30.560 21.090 30.790 22.260 ;
      RECT 30.560 22.260 30.930 22.600 ;
      RECT 32.400 22.260 33.370 22.600 ;
      RECT 33.140 21.090 33.370 22.260 ;
      RECT 24.980 10.210 25.320 10.550 ;
      RECT 30.595 22.780 30.935 23.120 ;
      RECT 32.395 22.780 32.735 23.120 ;
      RECT 25.215 12.230 25.445 14.400 ;
      RECT 25.215 14.400 25.915 14.740 ;
      RECT 37.415 14.400 37.925 14.740 ;
      RECT 37.695 12.230 37.925 14.400 ;
      RECT 37.695 21.090 37.925 23.260 ;
      RECT 39.275 21.090 39.505 23.260 ;
      RECT 37.695 23.260 40.215 23.600 ;
      RECT 40.215 21.090 40.445 23.600 ;
      RECT 42.735 21.090 42.965 23.260 ;
      RECT 42.735 23.260 43.145 23.600 ;
      RECT 38.485 12.230 38.715 14.400 ;
      RECT 38.485 14.400 38.945 14.740 ;
      RECT 37.415 23.860 41.795 24.200 ;
      RECT 41.795 21.090 42.025 24.200 ;
      RECT 39.215 14.400 39.655 14.740 ;
      RECT 39.425 12.230 39.655 14.400 ;
      RECT 42.815 9.090 43.610 9.430 ;
      RECT 43.380 6.920 43.610 9.090 ;
      RECT 42.215 14.400 42.965 14.740 ;
      RECT 42.735 12.230 42.965 14.400 ;
      RECT 38.610 24.980 38.950 25.320 ;
      RECT 43.415 14.400 44.695 14.740 ;
      RECT 44.465 12.230 44.695 14.400 ;
      RECT 29.270 9.280 29.500 12.050 ;
      RECT 29.270 12.050 34.430 12.390 ;
      RECT 34.430 9.280 34.660 12.390 ;
      RECT 39.210 25.630 39.550 25.970 ;
      RECT 41.010 25.630 41.350 25.970 ;
      RECT 29.995 12.570 30.335 12.910 ;
      RECT 23.955 27.000 24.185 29.170 ;
      RECT 23.955 29.170 25.535 29.510 ;
      RECT 25.535 27.000 25.765 29.510 ;
      RECT 41.010 10.210 41.350 10.550 ;
      RECT 40.685 27.000 40.915 29.170 ;
      RECT 40.685 29.170 42.265 29.510 ;
      RECT 42.265 27.000 42.495 29.510 ;
      RECT 39.860 6.730 40.090 7.920 ;
      RECT 42.090 6.730 42.320 8.920 ;
      RECT 44.670 6.390 44.900 8.920 ;
      RECT 39.860 6.390 44.670 6.730 ;
      RECT 32.995 13.220 33.335 13.560 ;
      RECT 40.215 12.230 40.445 15.940 ;
      RECT 40.445 15.600 43.145 15.940 ;
      RECT 39.895 27.000 40.125 29.770 ;
      RECT 39.895 29.770 43.745 30.110 ;
      RECT 43.055 27.000 43.285 29.770 ;
      RECT 30.560 6.320 30.790 7.390 ;
      RECT 30.560 7.390 33.140 7.730 ;
      RECT 33.140 6.320 33.370 7.730 ;
      RECT 31.195 7.910 31.535 8.250 ;
      RECT 38.955 27.000 39.185 30.710 ;
      RECT 39.185 30.370 42.545 30.710 ;
      RECT 24.380 10.860 24.720 11.200 ;
      RECT 25.580 16.120 25.920 16.460 ;
      RECT 38.610 16.120 38.950 16.460 ;
      RECT 60.610 10.210 60.950 10.550 ;
      RECT 65.410 10.210 65.750 10.550 ;
      RECT 63.915 21.090 64.145 24.460 ;
      RECT 64.855 21.090 65.085 24.460 ;
      RECT 58.815 24.460 66.435 24.800 ;
      RECT 66.435 21.090 66.665 24.800 ;
      RECT 57.155 45.715 57.495 46.365 ;
      RECT 63.455 45.715 63.795 46.365 ;
      RECT 79.255 45.715 79.595 46.365 ;
      RECT 85.555 45.715 85.895 46.365 ;
      RECT 62.415 9.090 63.210 9.430 ;
      RECT 62.980 6.920 63.210 9.090 ;
      RECT 50.210 9.260 50.550 9.600 ;
      RECT 58.210 24.980 58.550 25.320 ;
      RECT 51.410 25.030 51.750 25.370 ;
      RECT 64.810 10.860 65.150 11.200 ;
      RECT 46.410 16.120 46.750 16.460 ;
      RECT 49.060 46.220 49.820 46.560 ;
      RECT 49.590 45.050 49.820 46.220 ;
      RECT 50.860 46.220 52.110 46.560 ;
      RECT 52.110 45.050 52.340 46.560 ;
      RECT 53.860 46.220 54.860 46.560 ;
      RECT 54.630 45.050 54.860 46.220 ;
      RECT 71.160 46.220 71.920 46.560 ;
      RECT 71.690 45.050 71.920 46.220 ;
      RECT 72.960 46.220 74.210 46.560 ;
      RECT 74.210 45.050 74.440 46.560 ;
      RECT 75.960 46.220 76.960 46.560 ;
      RECT 76.730 45.050 76.960 46.220 ;
      RECT 58.210 16.120 58.550 16.460 ;
      RECT 61.810 16.120 62.150 16.460 ;
      RECT 52.055 46.740 52.395 47.080 ;
      RECT 74.155 46.740 74.495 47.080 ;
      RECT 58.810 25.630 59.150 25.970 ;
      RECT 60.610 25.630 60.950 25.970 ;
      RECT 66.010 16.120 66.350 16.460 ;
      RECT 53.210 9.260 53.550 9.600 ;
      RECT 50.805 6.390 51.145 6.730 ;
      RECT 50.805 6.730 51.035 7.920 ;
      RECT 50.015 6.920 50.245 8.090 ;
      RECT 50.015 8.090 51.595 8.430 ;
      RECT 51.595 6.920 51.825 8.430 ;
      RECT 60.285 27.000 60.515 29.170 ;
      RECT 60.285 29.170 61.865 29.510 ;
      RECT 61.865 27.000 62.095 29.510 ;
      RECT 48.800 50.870 49.030 53.060 ;
      RECT 50.380 50.530 50.610 53.060 ;
      RECT 48.800 50.530 50.380 50.870 ;
      RECT 51.320 50.870 51.550 53.060 ;
      RECT 52.900 50.530 53.130 53.060 ;
      RECT 51.320 50.530 52.900 50.870 ;
      RECT 53.840 50.870 54.070 53.060 ;
      RECT 55.420 50.530 55.650 53.060 ;
      RECT 53.840 50.530 55.420 50.870 ;
      RECT 70.900 50.870 71.130 53.060 ;
      RECT 72.480 50.530 72.710 53.060 ;
      RECT 70.900 50.530 72.480 50.870 ;
      RECT 73.420 50.870 73.650 53.060 ;
      RECT 75.000 50.530 75.230 53.060 ;
      RECT 73.420 50.530 75.000 50.870 ;
      RECT 75.940 50.870 76.170 53.060 ;
      RECT 77.520 50.530 77.750 53.060 ;
      RECT 75.940 50.530 77.520 50.870 ;
      RECT 64.385 27.000 64.615 29.170 ;
      RECT 64.385 29.170 65.965 29.510 ;
      RECT 65.965 27.000 66.195 29.510 ;
      RECT 60.400 6.920 60.630 9.690 ;
      RECT 57.015 9.690 65.560 10.030 ;
      RECT 65.560 6.920 65.790 10.030 ;
      RECT 57.015 14.400 57.525 14.740 ;
      RECT 57.295 12.230 57.525 14.400 ;
      RECT 47.010 16.770 47.350 17.110 ;
      RECT 58.810 16.770 59.150 17.110 ;
      RECT 59.495 27.000 59.725 29.770 ;
      RECT 59.495 29.770 63.345 30.110 ;
      RECT 62.655 27.000 62.885 29.770 ;
      RECT 49.060 53.230 49.820 53.570 ;
      RECT 49.590 51.060 49.820 53.230 ;
      RECT 50.860 53.230 52.340 53.570 ;
      RECT 52.110 51.060 52.340 53.230 ;
      RECT 53.860 53.230 54.860 53.570 ;
      RECT 54.630 51.060 54.860 53.230 ;
      RECT 71.160 53.230 71.920 53.570 ;
      RECT 71.690 51.060 71.920 53.230 ;
      RECT 72.960 53.230 74.440 53.570 ;
      RECT 74.210 51.060 74.440 53.230 ;
      RECT 75.960 53.230 76.960 53.570 ;
      RECT 76.730 51.060 76.960 53.230 ;
      RECT 63.595 27.000 63.825 29.770 ;
      RECT 63.595 29.770 66.755 30.110 ;
      RECT 66.755 27.000 66.985 30.110 ;
      RECT 63.010 16.770 63.350 17.110 ;
      RECT 51.455 53.750 51.795 54.090 ;
      RECT 73.555 53.750 73.895 54.090 ;
      RECT 66.610 16.770 66.950 17.110 ;
      RECT 58.555 27.000 58.785 30.710 ;
      RECT 58.785 30.370 62.145 30.710 ;
      RECT 58.085 12.230 58.315 14.400 ;
      RECT 58.085 14.400 58.545 14.740 ;
      RECT 58.815 14.400 59.255 14.740 ;
      RECT 59.025 12.230 59.255 14.400 ;
      RECT 56.975 27.000 57.205 31.310 ;
      RECT 57.205 30.970 66.945 31.310 ;
      RECT 61.815 14.400 62.565 14.740 ;
      RECT 62.335 12.230 62.565 14.400 ;
      RECT 63.015 14.400 64.295 14.740 ;
      RECT 64.065 12.230 64.295 14.400 ;
      RECT 65.645 12.230 65.875 14.400 ;
      RECT 65.645 14.400 66.345 14.740 ;
      RECT 59.460 6.730 59.690 7.920 ;
      RECT 61.690 6.730 61.920 8.920 ;
      RECT 64.270 6.390 64.500 8.920 ;
      RECT 59.460 6.390 64.270 6.730 ;
      RECT 51.410 8.610 51.750 8.950 ;
      RECT 47.010 31.490 47.350 31.830 ;
      RECT 58.210 31.490 58.550 31.830 ;
      RECT 61.810 31.490 62.150 31.830 ;
      RECT 66.610 31.490 66.950 31.830 ;
      RECT 60.755 12.230 60.985 15.340 ;
      RECT 60.985 15.000 66.945 15.340 ;
      RECT 52.535 6.920 52.765 8.090 ;
      RECT 52.535 8.090 53.545 8.430 ;
      RECT 57.295 21.090 57.525 23.260 ;
      RECT 58.875 21.090 59.105 23.260 ;
      RECT 57.295 23.260 59.815 23.600 ;
      RECT 59.815 21.090 60.045 23.600 ;
      RECT 46.410 32.140 46.750 32.480 ;
      RECT 58.810 32.140 59.150 32.480 ;
      RECT 66.010 32.140 66.350 32.480 ;
      RECT 62.335 21.090 62.565 23.260 ;
      RECT 62.335 23.260 62.745 23.600 ;
      RECT 50.805 21.160 51.145 21.500 ;
      RECT 50.805 21.500 51.035 23.690 ;
      RECT 63.010 32.790 63.350 33.130 ;
      RECT 53.815 8.090 54.345 8.430 ;
      RECT 54.115 6.920 54.345 8.090 ;
      RECT 59.815 12.230 60.045 15.940 ;
      RECT 60.045 15.600 62.745 15.940 ;
      RECT 50.015 21.690 50.245 23.860 ;
      RECT 50.015 23.860 51.595 24.200 ;
      RECT 51.595 21.690 51.825 24.200 ;
      RECT 52.535 21.690 52.765 23.860 ;
      RECT 52.535 23.860 53.545 24.200 ;
      RECT 53.815 23.860 54.345 24.200 ;
      RECT 54.115 21.690 54.345 23.860 ;
      RECT 57.015 23.860 61.395 24.200 ;
      RECT 61.395 21.090 61.625 24.200 ;
      RECT 49.610 24.380 49.950 24.720 ;
      RECT 48.800 44.860 49.030 46.050 ;
      RECT 50.380 44.520 50.610 46.050 ;
      RECT 48.800 44.520 50.380 44.860 ;
      RECT 51.320 44.860 51.550 46.050 ;
      RECT 52.900 44.520 53.130 46.050 ;
      RECT 51.320 44.520 52.900 44.860 ;
      RECT 53.840 44.860 54.070 46.050 ;
      RECT 55.420 44.520 55.650 46.050 ;
      RECT 53.840 44.520 55.420 44.860 ;
      RECT 70.900 44.860 71.130 46.050 ;
      RECT 72.480 44.520 72.710 46.050 ;
      RECT 70.900 44.520 72.480 44.860 ;
      RECT 73.420 44.860 73.650 46.050 ;
      RECT 75.000 44.520 75.230 46.050 ;
      RECT 73.420 44.520 75.000 44.860 ;
      RECT 75.940 44.860 76.170 46.050 ;
      RECT 77.520 44.520 77.750 46.050 ;
      RECT 75.940 44.520 77.520 44.860 ;
      RECT 53.210 24.380 53.550 24.720 ;
    LAYER met2 ;
      RECT 45.815 10.215 45.840 10.545 ;
      RECT 45.795 41.945 46.165 42.315 ;
      RECT 46.120 10.215 46.145 10.545 ;
      RECT 45.840 10.200 46.120 41.945 ;
      RECT 6.660 46.225 6.685 46.555 ;
      RECT 6.640 55.755 7.010 56.125 ;
      RECT 6.685 53.565 6.965 55.755 ;
      RECT 6.660 53.235 6.990 53.565 ;
      RECT 6.965 46.225 6.990 46.555 ;
      RECT 6.685 46.210 6.965 53.235 ;
      RECT 19.240 55.755 19.610 56.125 ;
      RECT 19.285 46.205 19.565 55.755 ;
      RECT 19.260 45.875 19.590 46.205 ;
      RECT 28.760 46.225 28.785 46.555 ;
      RECT 28.740 55.755 29.110 56.125 ;
      RECT 28.785 53.565 29.065 55.755 ;
      RECT 28.760 53.235 29.090 53.565 ;
      RECT 29.065 46.225 29.090 46.555 ;
      RECT 28.785 46.210 29.065 53.235 ;
      RECT 41.340 55.755 41.710 56.125 ;
      RECT 41.385 46.205 41.665 55.755 ;
      RECT 41.360 45.875 41.690 46.205 ;
      RECT 50.860 46.225 50.885 46.555 ;
      RECT 50.840 55.755 51.210 56.125 ;
      RECT 50.885 53.565 51.165 55.755 ;
      RECT 50.860 53.235 51.190 53.565 ;
      RECT 51.165 46.225 51.190 46.555 ;
      RECT 50.885 46.210 51.165 53.235 ;
      RECT 63.440 55.755 63.810 56.125 ;
      RECT 63.485 46.205 63.765 55.755 ;
      RECT 63.460 45.875 63.790 46.205 ;
      RECT 72.960 46.225 72.985 46.555 ;
      RECT 72.940 55.755 73.310 56.125 ;
      RECT 72.985 53.565 73.265 55.755 ;
      RECT 72.960 53.235 73.290 53.565 ;
      RECT 73.265 46.225 73.290 46.555 ;
      RECT 72.985 46.210 73.265 53.235 ;
      RECT 85.540 55.755 85.910 56.125 ;
      RECT 85.585 46.205 85.865 55.755 ;
      RECT 85.560 45.875 85.890 46.205 ;
      RECT 4.860 46.225 4.885 46.555 ;
      RECT 4.840 56.455 5.210 56.825 ;
      RECT 4.885 53.565 5.165 56.455 ;
      RECT 4.860 53.235 5.190 53.565 ;
      RECT 5.165 46.225 5.190 46.555 ;
      RECT 4.885 46.210 5.165 53.235 ;
      RECT 12.940 56.455 13.310 56.825 ;
      RECT 12.985 46.205 13.265 56.455 ;
      RECT 12.960 45.875 13.290 46.205 ;
      RECT 26.960 46.225 26.985 46.555 ;
      RECT 26.940 56.455 27.310 56.825 ;
      RECT 26.985 53.565 27.265 56.455 ;
      RECT 26.960 53.235 27.290 53.565 ;
      RECT 27.265 46.225 27.290 46.555 ;
      RECT 26.985 46.210 27.265 53.235 ;
      RECT 35.040 56.455 35.410 56.825 ;
      RECT 35.085 46.205 35.365 56.455 ;
      RECT 35.060 45.875 35.390 46.205 ;
      RECT 49.060 46.225 49.085 46.555 ;
      RECT 49.040 56.455 49.410 56.825 ;
      RECT 49.085 53.565 49.365 56.455 ;
      RECT 49.060 53.235 49.390 53.565 ;
      RECT 49.365 46.225 49.390 46.555 ;
      RECT 49.085 46.210 49.365 53.235 ;
      RECT 57.140 56.455 57.510 56.825 ;
      RECT 57.185 46.205 57.465 56.455 ;
      RECT 57.160 45.875 57.490 46.205 ;
      RECT 71.160 46.225 71.185 46.555 ;
      RECT 71.140 56.455 71.510 56.825 ;
      RECT 71.185 53.565 71.465 56.455 ;
      RECT 71.160 53.235 71.490 53.565 ;
      RECT 71.465 46.225 71.490 46.555 ;
      RECT 71.185 46.210 71.465 53.235 ;
      RECT 79.240 56.455 79.610 56.825 ;
      RECT 79.285 46.205 79.565 56.455 ;
      RECT 79.260 45.875 79.590 46.205 ;
      RECT 3.315 71.825 3.685 72.195 ;
      RECT 3.360 36.715 3.640 71.825 ;
      RECT 3.315 36.345 3.685 36.715 ;
      RECT 10.560 44.525 10.585 44.855 ;
      RECT 10.585 102.945 10.865 102.960 ;
      RECT 10.560 102.615 10.890 102.945 ;
      RECT 10.585 102.265 10.865 102.615 ;
      RECT 10.540 101.895 10.910 102.265 ;
      RECT 10.585 75.815 10.865 101.895 ;
      RECT 10.560 75.485 10.890 75.815 ;
      RECT 10.585 58.880 10.865 75.485 ;
      RECT 10.560 58.550 10.890 58.880 ;
      RECT 10.585 50.865 10.865 58.550 ;
      RECT 10.560 50.535 10.890 50.865 ;
      RECT 10.865 44.525 10.890 44.855 ;
      RECT 10.585 44.510 10.865 50.535 ;
      RECT 32.660 44.525 32.685 44.855 ;
      RECT 32.685 102.945 32.965 102.960 ;
      RECT 32.660 102.615 32.990 102.945 ;
      RECT 32.685 102.265 32.965 102.615 ;
      RECT 32.640 101.895 33.010 102.265 ;
      RECT 32.685 75.815 32.965 101.895 ;
      RECT 32.660 75.485 32.990 75.815 ;
      RECT 32.685 58.880 32.965 75.485 ;
      RECT 32.660 58.550 32.990 58.880 ;
      RECT 32.685 50.865 32.965 58.550 ;
      RECT 32.660 50.535 32.990 50.865 ;
      RECT 32.965 44.525 32.990 44.855 ;
      RECT 32.685 44.510 32.965 50.535 ;
      RECT 54.760 44.525 54.785 44.855 ;
      RECT 54.785 102.945 55.065 102.960 ;
      RECT 54.760 102.615 55.090 102.945 ;
      RECT 54.785 102.265 55.065 102.615 ;
      RECT 54.740 101.895 55.110 102.265 ;
      RECT 54.785 75.815 55.065 101.895 ;
      RECT 54.760 75.485 55.090 75.815 ;
      RECT 54.785 58.880 55.065 75.485 ;
      RECT 54.760 58.550 55.090 58.880 ;
      RECT 54.785 50.865 55.065 58.550 ;
      RECT 54.760 50.535 55.090 50.865 ;
      RECT 55.065 44.525 55.090 44.855 ;
      RECT 54.785 44.510 55.065 50.535 ;
      RECT 76.860 44.525 76.885 44.855 ;
      RECT 76.885 102.945 77.165 102.960 ;
      RECT 76.860 102.615 77.190 102.945 ;
      RECT 76.885 102.265 77.165 102.615 ;
      RECT 76.840 101.895 77.210 102.265 ;
      RECT 76.885 75.815 77.165 101.895 ;
      RECT 76.860 75.485 77.190 75.815 ;
      RECT 76.885 58.880 77.165 75.485 ;
      RECT 76.860 58.550 77.190 58.880 ;
      RECT 76.885 50.865 77.165 58.550 ;
      RECT 76.860 50.535 77.190 50.865 ;
      RECT 77.165 44.525 77.190 44.855 ;
      RECT 76.885 44.510 77.165 50.535 ;
      RECT 2.715 108.005 3.085 108.375 ;
      RECT 2.760 37.415 3.040 108.005 ;
      RECT 2.715 37.045 3.085 37.415 ;
      RECT 0.300 0.000 1.100 108.690 ;
      RECT 1.500 1.200 2.300 109.890 ;
      RECT 49.385 58.880 49.665 58.895 ;
      RECT 49.360 58.550 49.690 58.880 ;
      RECT 49.385 58.115 49.665 58.550 ;
      RECT 49.340 57.745 49.710 58.115 ;
      RECT 55.340 71.825 55.710 72.195 ;
      RECT 77.440 71.825 77.810 72.195 ;
      RECT 54.160 71.325 54.185 71.655 ;
      RECT 54.185 76.335 54.465 76.350 ;
      RECT 54.160 76.005 54.490 76.335 ;
      RECT 54.185 73.015 54.465 76.005 ;
      RECT 54.160 72.685 54.490 73.015 ;
      RECT 54.465 71.325 54.490 71.655 ;
      RECT 54.185 71.310 54.465 72.685 ;
      RECT 76.260 71.325 76.285 71.655 ;
      RECT 76.285 76.335 76.565 76.350 ;
      RECT 76.260 76.005 76.590 76.335 ;
      RECT 76.285 73.015 76.565 76.005 ;
      RECT 76.260 72.685 76.590 73.015 ;
      RECT 76.565 71.325 76.590 71.655 ;
      RECT 76.285 71.310 76.565 72.685 ;
      RECT 49.360 71.325 49.385 71.655 ;
      RECT 49.385 80.545 49.665 80.560 ;
      RECT 49.360 80.215 49.690 80.545 ;
      RECT 49.385 77.735 49.665 80.215 ;
      RECT 49.360 77.405 49.690 77.735 ;
      RECT 49.665 71.325 49.690 71.655 ;
      RECT 49.385 71.310 49.665 77.405 ;
      RECT 71.460 71.325 71.485 71.655 ;
      RECT 71.485 80.545 71.765 80.560 ;
      RECT 71.460 80.215 71.790 80.545 ;
      RECT 71.485 77.735 71.765 80.215 ;
      RECT 71.460 77.405 71.790 77.735 ;
      RECT 71.765 71.325 71.790 71.655 ;
      RECT 71.485 71.310 71.765 77.405 ;
      RECT 54.160 79.375 54.185 79.705 ;
      RECT 54.185 83.115 54.465 83.130 ;
      RECT 54.160 82.785 54.490 83.115 ;
      RECT 54.185 80.465 54.465 82.785 ;
      RECT 54.140 80.095 54.510 80.465 ;
      RECT 54.465 79.375 54.490 79.705 ;
      RECT 54.185 79.360 54.465 80.095 ;
      RECT 76.260 79.375 76.285 79.705 ;
      RECT 76.285 83.115 76.565 83.130 ;
      RECT 76.260 82.785 76.590 83.115 ;
      RECT 76.285 80.465 76.565 82.785 ;
      RECT 76.240 80.095 76.610 80.465 ;
      RECT 76.565 79.375 76.590 79.705 ;
      RECT 76.285 79.360 76.565 80.095 ;
      RECT 49.960 79.375 49.985 79.705 ;
      RECT 49.985 83.675 50.265 83.690 ;
      RECT 49.960 83.345 50.290 83.675 ;
      RECT 49.985 82.565 50.265 83.345 ;
      RECT 49.940 82.195 50.310 82.565 ;
      RECT 50.265 79.375 50.290 79.705 ;
      RECT 49.985 79.360 50.265 82.195 ;
      RECT 72.060 79.375 72.085 79.705 ;
      RECT 72.085 83.675 72.365 83.690 ;
      RECT 72.060 83.345 72.390 83.675 ;
      RECT 72.085 82.565 72.365 83.345 ;
      RECT 72.040 82.195 72.410 82.565 ;
      RECT 72.365 79.375 72.390 79.705 ;
      RECT 72.085 79.360 72.365 82.195 ;
      RECT 55.360 74.885 55.385 75.215 ;
      RECT 55.385 86.605 55.665 86.620 ;
      RECT 55.360 86.275 55.690 86.605 ;
      RECT 55.665 74.885 55.690 75.215 ;
      RECT 55.385 74.870 55.665 86.275 ;
      RECT 77.460 74.885 77.485 75.215 ;
      RECT 77.485 86.605 77.765 86.620 ;
      RECT 77.460 86.275 77.790 86.605 ;
      RECT 77.765 74.885 77.790 75.215 ;
      RECT 77.485 74.870 77.765 86.275 ;
      RECT 51.760 78.855 51.785 79.185 ;
      RECT 51.785 96.185 52.065 96.200 ;
      RECT 51.760 95.855 52.090 96.185 ;
      RECT 51.785 94.825 52.065 95.855 ;
      RECT 51.760 94.495 52.090 94.825 ;
      RECT 51.785 90.165 52.065 94.495 ;
      RECT 51.760 89.835 52.090 90.165 ;
      RECT 51.785 82.595 52.065 89.835 ;
      RECT 51.760 82.265 52.090 82.595 ;
      RECT 52.065 78.855 52.090 79.185 ;
      RECT 51.785 78.840 52.065 82.265 ;
      RECT 52.360 78.855 52.385 79.185 ;
      RECT 52.385 96.185 52.665 96.200 ;
      RECT 52.360 95.855 52.690 96.185 ;
      RECT 52.385 94.225 52.665 95.855 ;
      RECT 52.360 93.895 52.690 94.225 ;
      RECT 52.385 90.165 52.665 93.895 ;
      RECT 52.360 89.835 52.690 90.165 ;
      RECT 52.385 81.995 52.665 89.835 ;
      RECT 52.360 81.665 52.690 81.995 ;
      RECT 52.665 78.855 52.690 79.185 ;
      RECT 52.385 78.840 52.665 81.665 ;
      RECT 73.860 78.855 73.885 79.185 ;
      RECT 73.885 96.185 74.165 96.200 ;
      RECT 73.860 95.855 74.190 96.185 ;
      RECT 73.885 94.825 74.165 95.855 ;
      RECT 73.860 94.495 74.190 94.825 ;
      RECT 73.885 90.165 74.165 94.495 ;
      RECT 73.860 89.835 74.190 90.165 ;
      RECT 73.885 82.595 74.165 89.835 ;
      RECT 73.860 82.265 74.190 82.595 ;
      RECT 74.165 78.855 74.190 79.185 ;
      RECT 73.885 78.840 74.165 82.265 ;
      RECT 74.460 78.855 74.485 79.185 ;
      RECT 74.485 96.185 74.765 96.200 ;
      RECT 74.460 95.855 74.790 96.185 ;
      RECT 74.485 94.225 74.765 95.855 ;
      RECT 74.460 93.895 74.790 94.225 ;
      RECT 74.485 90.165 74.765 93.895 ;
      RECT 74.460 89.835 74.790 90.165 ;
      RECT 74.485 81.995 74.765 89.835 ;
      RECT 74.460 81.665 74.790 81.995 ;
      RECT 74.765 78.855 74.790 79.185 ;
      RECT 74.485 78.840 74.765 81.665 ;
      RECT 50.560 61.915 50.585 62.245 ;
      RECT 50.585 98.385 50.865 98.400 ;
      RECT 50.560 98.055 50.890 98.385 ;
      RECT 50.585 68.695 50.865 98.055 ;
      RECT 50.560 68.365 50.890 68.695 ;
      RECT 50.585 65.655 50.865 68.365 ;
      RECT 50.560 65.325 50.890 65.655 ;
      RECT 50.865 61.915 50.890 62.245 ;
      RECT 50.585 61.900 50.865 65.325 ;
      RECT 72.660 61.915 72.685 62.245 ;
      RECT 72.685 98.385 72.965 98.400 ;
      RECT 72.660 98.055 72.990 98.385 ;
      RECT 72.685 68.695 72.965 98.055 ;
      RECT 72.660 68.365 72.990 68.695 ;
      RECT 72.685 65.655 72.965 68.365 ;
      RECT 72.660 65.325 72.990 65.655 ;
      RECT 72.965 61.915 72.990 62.245 ;
      RECT 72.685 61.900 72.965 65.325 ;
      RECT 55.340 98.555 55.710 98.925 ;
      RECT 77.440 98.555 77.810 98.925 ;
      RECT 51.185 84.655 51.465 99.020 ;
      RECT 51.160 84.325 51.490 84.655 ;
      RECT 51.185 77.410 51.465 84.325 ;
      RECT 52.985 84.655 53.265 99.020 ;
      RECT 52.960 84.325 53.290 84.655 ;
      RECT 52.985 77.410 53.265 84.325 ;
      RECT 73.285 84.655 73.565 99.020 ;
      RECT 73.260 84.325 73.590 84.655 ;
      RECT 73.285 77.410 73.565 84.325 ;
      RECT 75.085 84.655 75.365 99.020 ;
      RECT 75.060 84.325 75.390 84.655 ;
      RECT 75.085 77.410 75.365 84.325 ;
      RECT 67.400 101.895 67.770 102.265 ;
      RECT 67.445 87.875 67.725 101.895 ;
      RECT 67.400 87.505 67.770 87.875 ;
      RECT 89.500 101.895 89.870 102.265 ;
      RECT 89.545 87.875 89.825 101.895 ;
      RECT 89.500 87.505 89.870 87.875 ;
      RECT 71.485 58.880 71.765 58.895 ;
      RECT 71.460 58.550 71.790 58.880 ;
      RECT 71.485 58.115 71.765 58.550 ;
      RECT 71.440 57.745 71.810 58.115 ;
      RECT 51.760 61.395 51.785 61.725 ;
      RECT 51.785 66.495 52.065 66.510 ;
      RECT 51.760 66.165 52.090 66.495 ;
      RECT 51.785 65.135 52.065 66.165 ;
      RECT 51.760 64.805 52.090 65.135 ;
      RECT 52.065 61.395 52.090 61.725 ;
      RECT 51.785 61.380 52.065 64.805 ;
      RECT 52.360 61.395 52.385 61.725 ;
      RECT 52.385 66.495 52.665 66.510 ;
      RECT 52.360 66.165 52.690 66.495 ;
      RECT 52.385 64.535 52.665 66.165 ;
      RECT 52.360 64.205 52.690 64.535 ;
      RECT 52.665 61.395 52.690 61.725 ;
      RECT 52.385 61.380 52.665 64.205 ;
      RECT 73.860 61.395 73.885 61.725 ;
      RECT 73.885 66.495 74.165 66.510 ;
      RECT 73.860 66.165 74.190 66.495 ;
      RECT 73.885 65.135 74.165 66.165 ;
      RECT 73.860 64.805 74.190 65.135 ;
      RECT 74.165 61.395 74.190 61.725 ;
      RECT 73.885 61.380 74.165 64.805 ;
      RECT 48.760 90.355 48.785 90.685 ;
      RECT 48.785 103.465 49.065 103.480 ;
      RECT 48.760 103.135 49.090 103.465 ;
      RECT 48.785 101.265 49.065 103.135 ;
      RECT 48.740 100.895 49.110 101.265 ;
      RECT 48.785 95.345 49.065 100.895 ;
      RECT 48.760 95.015 49.090 95.345 ;
      RECT 49.065 90.355 49.090 90.685 ;
      RECT 48.785 90.340 49.065 95.015 ;
      RECT 70.860 90.355 70.885 90.685 ;
      RECT 70.885 103.465 71.165 103.480 ;
      RECT 70.860 103.135 71.190 103.465 ;
      RECT 70.885 101.265 71.165 103.135 ;
      RECT 70.840 100.895 71.210 101.265 ;
      RECT 70.885 95.345 71.165 100.895 ;
      RECT 70.860 95.015 71.190 95.345 ;
      RECT 71.165 90.355 71.190 90.685 ;
      RECT 70.885 90.340 71.165 95.015 ;
      RECT 49.985 104.865 50.265 104.880 ;
      RECT 49.960 104.535 50.290 104.865 ;
      RECT 49.985 104.025 50.265 104.535 ;
      RECT 49.960 103.695 50.290 104.025 ;
      RECT 49.960 102.615 49.985 102.945 ;
      RECT 50.265 102.615 50.290 102.945 ;
      RECT 49.985 102.600 50.265 103.695 ;
      RECT 72.085 104.865 72.365 104.880 ;
      RECT 72.060 104.535 72.390 104.865 ;
      RECT 72.085 104.025 72.365 104.535 ;
      RECT 72.060 103.695 72.390 104.025 ;
      RECT 72.060 102.615 72.085 102.945 ;
      RECT 72.365 102.615 72.390 102.945 ;
      RECT 72.085 102.600 72.365 103.695 ;
      RECT 46.960 105.505 47.290 105.835 ;
      RECT 46.985 102.265 47.265 105.505 ;
      RECT 46.940 101.895 47.310 102.265 ;
      RECT 58.910 105.505 59.240 105.835 ;
      RECT 58.935 80.465 59.215 105.505 ;
      RECT 58.890 80.095 59.260 80.465 ;
      RECT 65.210 105.505 65.540 105.835 ;
      RECT 65.235 85.175 65.515 105.505 ;
      RECT 65.190 84.805 65.560 85.175 ;
      RECT 65.235 82.565 65.515 84.805 ;
      RECT 65.190 82.195 65.560 82.565 ;
      RECT 69.060 105.505 69.390 105.835 ;
      RECT 69.085 102.265 69.365 105.505 ;
      RECT 69.040 101.895 69.410 102.265 ;
      RECT 81.010 105.505 81.340 105.835 ;
      RECT 81.035 80.465 81.315 105.505 ;
      RECT 80.990 80.095 81.360 80.465 ;
      RECT 87.310 105.505 87.640 105.835 ;
      RECT 87.335 85.175 87.615 105.505 ;
      RECT 87.290 84.805 87.660 85.175 ;
      RECT 87.335 82.565 87.615 84.805 ;
      RECT 87.290 82.195 87.660 82.565 ;
      RECT 91.160 105.505 91.490 105.835 ;
      RECT 91.185 102.265 91.465 105.505 ;
      RECT 91.140 101.895 91.510 102.265 ;
      RECT 49.360 84.325 49.385 84.655 ;
      RECT 49.385 107.065 49.665 107.080 ;
      RECT 49.360 106.735 49.690 107.065 ;
      RECT 49.665 84.325 49.690 84.655 ;
      RECT 49.385 84.310 49.665 106.735 ;
      RECT 71.460 84.325 71.485 84.655 ;
      RECT 71.485 107.065 71.765 107.080 ;
      RECT 71.460 106.735 71.790 107.065 ;
      RECT 71.765 84.325 71.790 84.655 ;
      RECT 71.485 84.310 71.765 106.735 ;
      RECT 53.585 107.585 53.865 107.600 ;
      RECT 53.560 107.255 53.890 107.585 ;
      RECT 53.585 98.385 53.865 107.255 ;
      RECT 53.560 98.055 53.890 98.385 ;
      RECT 53.585 76.895 53.865 98.055 ;
      RECT 53.560 76.565 53.890 76.895 ;
      RECT 53.585 68.695 53.865 76.565 ;
      RECT 53.560 68.565 53.890 68.695 ;
      RECT 53.540 68.195 53.910 68.565 ;
      RECT 75.685 107.585 75.965 107.600 ;
      RECT 75.660 107.255 75.990 107.585 ;
      RECT 75.685 98.385 75.965 107.255 ;
      RECT 75.660 98.055 75.990 98.385 ;
      RECT 75.685 76.895 75.965 98.055 ;
      RECT 75.660 76.565 75.990 76.895 ;
      RECT 75.685 68.695 75.965 76.565 ;
      RECT 75.660 68.565 75.990 68.695 ;
      RECT 75.640 68.195 76.010 68.565 ;
      RECT 74.460 61.395 74.485 61.725 ;
      RECT 74.485 66.495 74.765 66.510 ;
      RECT 74.460 66.165 74.790 66.495 ;
      RECT 74.485 64.535 74.765 66.165 ;
      RECT 74.460 64.205 74.790 64.535 ;
      RECT 74.765 61.395 74.790 61.725 ;
      RECT 74.485 61.380 74.765 64.205 ;
      RECT 62.740 108.005 63.110 108.375 ;
      RECT 62.785 105.835 63.065 108.005 ;
      RECT 62.760 105.505 63.090 105.835 ;
      RECT 84.840 108.005 85.210 108.375 ;
      RECT 84.885 105.835 85.165 108.005 ;
      RECT 84.860 105.505 85.190 105.835 ;
      RECT 48.740 68.955 49.110 69.325 ;
      RECT 48.760 68.885 49.090 68.955 ;
      RECT 48.785 68.870 49.065 68.885 ;
      RECT 49.640 109.305 50.010 109.675 ;
      RECT 49.660 108.235 49.990 109.305 ;
      RECT 54.440 109.305 54.810 109.675 ;
      RECT 54.460 108.235 54.790 109.305 ;
      RECT 71.740 109.305 72.110 109.675 ;
      RECT 71.760 108.235 72.090 109.305 ;
      RECT 76.540 109.305 76.910 109.675 ;
      RECT 76.560 108.235 76.890 109.305 ;
      RECT 70.840 68.955 71.210 69.325 ;
      RECT 70.860 68.885 71.190 68.955 ;
      RECT 70.885 68.870 71.165 68.885 ;
      RECT 30.260 61.395 30.285 61.725 ;
      RECT 30.285 66.495 30.565 66.510 ;
      RECT 30.260 66.165 30.590 66.495 ;
      RECT 30.285 64.535 30.565 66.165 ;
      RECT 30.260 64.205 30.590 64.535 ;
      RECT 30.565 61.395 30.590 61.725 ;
      RECT 30.285 61.380 30.565 64.205 ;
      RECT 5.185 58.880 5.465 58.895 ;
      RECT 5.160 58.550 5.490 58.880 ;
      RECT 5.185 58.115 5.465 58.550 ;
      RECT 5.140 57.745 5.510 58.115 ;
      RECT 23.200 101.895 23.570 102.265 ;
      RECT 23.245 87.875 23.525 101.895 ;
      RECT 23.200 87.505 23.570 87.875 ;
      RECT 45.300 101.895 45.670 102.265 ;
      RECT 45.345 87.875 45.625 101.895 ;
      RECT 45.300 87.505 45.670 87.875 ;
      RECT 5.760 79.375 5.785 79.705 ;
      RECT 5.785 83.675 6.065 83.690 ;
      RECT 5.760 83.345 6.090 83.675 ;
      RECT 5.785 82.565 6.065 83.345 ;
      RECT 5.740 82.195 6.110 82.565 ;
      RECT 6.065 79.375 6.090 79.705 ;
      RECT 5.785 79.360 6.065 82.195 ;
      RECT 27.860 79.375 27.885 79.705 ;
      RECT 27.885 83.675 28.165 83.690 ;
      RECT 27.860 83.345 28.190 83.675 ;
      RECT 27.885 82.565 28.165 83.345 ;
      RECT 27.840 82.195 28.210 82.565 ;
      RECT 28.165 79.375 28.190 79.705 ;
      RECT 27.885 79.360 28.165 82.195 ;
      RECT 11.140 71.825 11.510 72.195 ;
      RECT 33.240 71.825 33.610 72.195 ;
      RECT 11.160 74.885 11.185 75.215 ;
      RECT 11.185 86.605 11.465 86.620 ;
      RECT 11.160 86.275 11.490 86.605 ;
      RECT 11.465 74.885 11.490 75.215 ;
      RECT 11.185 74.870 11.465 86.275 ;
      RECT 33.260 74.885 33.285 75.215 ;
      RECT 33.285 86.605 33.565 86.620 ;
      RECT 33.260 86.275 33.590 86.605 ;
      RECT 33.565 74.885 33.590 75.215 ;
      RECT 33.285 74.870 33.565 86.275 ;
      RECT 4.560 90.355 4.585 90.685 ;
      RECT 4.585 103.465 4.865 103.480 ;
      RECT 4.560 103.135 4.890 103.465 ;
      RECT 4.585 101.265 4.865 103.135 ;
      RECT 4.540 100.895 4.910 101.265 ;
      RECT 4.585 95.345 4.865 100.895 ;
      RECT 4.560 95.015 4.890 95.345 ;
      RECT 4.865 90.355 4.890 90.685 ;
      RECT 4.585 90.340 4.865 95.015 ;
      RECT 26.660 90.355 26.685 90.685 ;
      RECT 26.685 103.465 26.965 103.480 ;
      RECT 26.660 103.135 26.990 103.465 ;
      RECT 26.685 101.265 26.965 103.135 ;
      RECT 26.640 100.895 27.010 101.265 ;
      RECT 26.685 95.345 26.965 100.895 ;
      RECT 26.660 95.015 26.990 95.345 ;
      RECT 26.965 90.355 26.990 90.685 ;
      RECT 26.685 90.340 26.965 95.015 ;
      RECT 27.285 58.880 27.565 58.895 ;
      RECT 27.260 58.550 27.590 58.880 ;
      RECT 27.285 58.115 27.565 58.550 ;
      RECT 27.240 57.745 27.610 58.115 ;
      RECT 7.560 61.395 7.585 61.725 ;
      RECT 7.585 66.495 7.865 66.510 ;
      RECT 7.560 66.165 7.890 66.495 ;
      RECT 7.585 65.135 7.865 66.165 ;
      RECT 7.560 64.805 7.890 65.135 ;
      RECT 7.865 61.395 7.890 61.725 ;
      RECT 7.585 61.380 7.865 64.805 ;
      RECT 5.785 104.865 6.065 104.880 ;
      RECT 5.760 104.535 6.090 104.865 ;
      RECT 5.785 104.025 6.065 104.535 ;
      RECT 5.760 103.695 6.090 104.025 ;
      RECT 5.760 102.615 5.785 102.945 ;
      RECT 6.065 102.615 6.090 102.945 ;
      RECT 5.785 102.600 6.065 103.695 ;
      RECT 27.885 104.865 28.165 104.880 ;
      RECT 27.860 104.535 28.190 104.865 ;
      RECT 27.885 104.025 28.165 104.535 ;
      RECT 27.860 103.695 28.190 104.025 ;
      RECT 27.860 102.615 27.885 102.945 ;
      RECT 28.165 102.615 28.190 102.945 ;
      RECT 27.885 102.600 28.165 103.695 ;
      RECT 7.560 78.855 7.585 79.185 ;
      RECT 7.585 96.185 7.865 96.200 ;
      RECT 7.560 95.855 7.890 96.185 ;
      RECT 7.585 94.825 7.865 95.855 ;
      RECT 7.560 94.495 7.890 94.825 ;
      RECT 7.585 90.165 7.865 94.495 ;
      RECT 7.560 89.835 7.890 90.165 ;
      RECT 7.585 82.595 7.865 89.835 ;
      RECT 7.560 82.265 7.890 82.595 ;
      RECT 7.865 78.855 7.890 79.185 ;
      RECT 7.585 78.840 7.865 82.265 ;
      RECT 8.160 78.855 8.185 79.185 ;
      RECT 8.185 96.185 8.465 96.200 ;
      RECT 8.160 95.855 8.490 96.185 ;
      RECT 8.185 94.225 8.465 95.855 ;
      RECT 8.160 93.895 8.490 94.225 ;
      RECT 8.185 90.165 8.465 93.895 ;
      RECT 8.160 89.835 8.490 90.165 ;
      RECT 8.185 81.995 8.465 89.835 ;
      RECT 8.160 81.665 8.490 81.995 ;
      RECT 8.465 78.855 8.490 79.185 ;
      RECT 8.185 78.840 8.465 81.665 ;
      RECT 14.710 105.505 15.040 105.835 ;
      RECT 14.735 80.465 15.015 105.505 ;
      RECT 14.690 80.095 15.060 80.465 ;
      RECT 21.010 105.505 21.340 105.835 ;
      RECT 21.035 85.175 21.315 105.505 ;
      RECT 20.990 84.805 21.360 85.175 ;
      RECT 21.035 82.565 21.315 84.805 ;
      RECT 20.990 82.195 21.360 82.565 ;
      RECT 24.860 105.505 25.190 105.835 ;
      RECT 24.885 102.265 25.165 105.505 ;
      RECT 24.840 101.895 25.210 102.265 ;
      RECT 36.810 105.505 37.140 105.835 ;
      RECT 36.835 80.465 37.115 105.505 ;
      RECT 36.790 80.095 37.160 80.465 ;
      RECT 43.110 105.505 43.440 105.835 ;
      RECT 43.135 85.175 43.415 105.505 ;
      RECT 43.090 84.805 43.460 85.175 ;
      RECT 43.135 82.565 43.415 84.805 ;
      RECT 43.090 82.195 43.460 82.565 ;
      RECT 29.660 78.855 29.685 79.185 ;
      RECT 29.685 96.185 29.965 96.200 ;
      RECT 29.660 95.855 29.990 96.185 ;
      RECT 29.685 94.825 29.965 95.855 ;
      RECT 29.660 94.495 29.990 94.825 ;
      RECT 29.685 90.165 29.965 94.495 ;
      RECT 29.660 89.835 29.990 90.165 ;
      RECT 29.685 82.595 29.965 89.835 ;
      RECT 29.660 82.265 29.990 82.595 ;
      RECT 29.965 78.855 29.990 79.185 ;
      RECT 29.685 78.840 29.965 82.265 ;
      RECT 30.260 78.855 30.285 79.185 ;
      RECT 30.285 96.185 30.565 96.200 ;
      RECT 30.260 95.855 30.590 96.185 ;
      RECT 30.285 94.225 30.565 95.855 ;
      RECT 30.260 93.895 30.590 94.225 ;
      RECT 30.285 90.165 30.565 93.895 ;
      RECT 30.260 89.835 30.590 90.165 ;
      RECT 30.285 81.995 30.565 89.835 ;
      RECT 30.260 81.665 30.590 81.995 ;
      RECT 30.565 78.855 30.590 79.185 ;
      RECT 30.285 78.840 30.565 81.665 ;
      RECT 9.960 71.325 9.985 71.655 ;
      RECT 9.985 76.335 10.265 76.350 ;
      RECT 9.960 76.005 10.290 76.335 ;
      RECT 9.985 73.015 10.265 76.005 ;
      RECT 9.960 72.685 10.290 73.015 ;
      RECT 10.265 71.325 10.290 71.655 ;
      RECT 9.985 71.310 10.265 72.685 ;
      RECT 32.060 71.325 32.085 71.655 ;
      RECT 32.085 76.335 32.365 76.350 ;
      RECT 32.060 76.005 32.390 76.335 ;
      RECT 32.085 73.015 32.365 76.005 ;
      RECT 32.060 72.685 32.390 73.015 ;
      RECT 32.365 71.325 32.390 71.655 ;
      RECT 32.085 71.310 32.365 72.685 ;
      RECT 8.160 61.395 8.185 61.725 ;
      RECT 8.185 66.495 8.465 66.510 ;
      RECT 8.160 66.165 8.490 66.495 ;
      RECT 8.185 64.535 8.465 66.165 ;
      RECT 8.160 64.205 8.490 64.535 ;
      RECT 8.465 61.395 8.490 61.725 ;
      RECT 8.185 61.380 8.465 64.205 ;
      RECT 4.540 68.955 4.910 69.325 ;
      RECT 4.560 68.885 4.890 68.955 ;
      RECT 4.585 68.870 4.865 68.885 ;
      RECT 6.360 61.915 6.385 62.245 ;
      RECT 6.385 98.385 6.665 98.400 ;
      RECT 6.360 98.055 6.690 98.385 ;
      RECT 6.385 68.695 6.665 98.055 ;
      RECT 6.360 68.365 6.690 68.695 ;
      RECT 6.385 65.655 6.665 68.365 ;
      RECT 6.360 65.325 6.690 65.655 ;
      RECT 6.665 61.915 6.690 62.245 ;
      RECT 6.385 61.900 6.665 65.325 ;
      RECT 5.160 84.325 5.185 84.655 ;
      RECT 5.185 107.065 5.465 107.080 ;
      RECT 5.160 106.735 5.490 107.065 ;
      RECT 5.465 84.325 5.490 84.655 ;
      RECT 5.185 84.310 5.465 106.735 ;
      RECT 27.260 84.325 27.285 84.655 ;
      RECT 27.285 107.065 27.565 107.080 ;
      RECT 27.260 106.735 27.590 107.065 ;
      RECT 27.565 84.325 27.590 84.655 ;
      RECT 27.285 84.310 27.565 106.735 ;
      RECT 28.460 61.915 28.485 62.245 ;
      RECT 28.485 98.385 28.765 98.400 ;
      RECT 28.460 98.055 28.790 98.385 ;
      RECT 28.485 68.695 28.765 98.055 ;
      RECT 28.460 68.365 28.790 68.695 ;
      RECT 28.485 65.655 28.765 68.365 ;
      RECT 28.460 65.325 28.790 65.655 ;
      RECT 28.765 61.915 28.790 62.245 ;
      RECT 28.485 61.900 28.765 65.325 ;
      RECT 5.160 71.325 5.185 71.655 ;
      RECT 5.185 80.545 5.465 80.560 ;
      RECT 5.160 80.215 5.490 80.545 ;
      RECT 5.185 77.735 5.465 80.215 ;
      RECT 5.160 77.405 5.490 77.735 ;
      RECT 5.465 71.325 5.490 71.655 ;
      RECT 5.185 71.310 5.465 77.405 ;
      RECT 9.385 107.585 9.665 107.600 ;
      RECT 9.360 107.255 9.690 107.585 ;
      RECT 9.385 98.385 9.665 107.255 ;
      RECT 9.360 98.055 9.690 98.385 ;
      RECT 9.385 76.895 9.665 98.055 ;
      RECT 9.360 76.565 9.690 76.895 ;
      RECT 9.385 68.695 9.665 76.565 ;
      RECT 9.360 68.565 9.690 68.695 ;
      RECT 9.340 68.195 9.710 68.565 ;
      RECT 31.485 107.585 31.765 107.600 ;
      RECT 31.460 107.255 31.790 107.585 ;
      RECT 31.485 98.385 31.765 107.255 ;
      RECT 31.460 98.055 31.790 98.385 ;
      RECT 31.485 76.895 31.765 98.055 ;
      RECT 31.460 76.565 31.790 76.895 ;
      RECT 31.485 68.695 31.765 76.565 ;
      RECT 31.460 68.565 31.790 68.695 ;
      RECT 31.440 68.195 31.810 68.565 ;
      RECT 27.260 71.325 27.285 71.655 ;
      RECT 27.285 80.545 27.565 80.560 ;
      RECT 27.260 80.215 27.590 80.545 ;
      RECT 27.285 77.735 27.565 80.215 ;
      RECT 27.260 77.405 27.590 77.735 ;
      RECT 27.565 71.325 27.590 71.655 ;
      RECT 27.285 71.310 27.565 77.405 ;
      RECT 11.140 98.555 11.510 98.925 ;
      RECT 33.240 98.555 33.610 98.925 ;
      RECT 18.540 108.005 18.910 108.375 ;
      RECT 18.585 105.835 18.865 108.005 ;
      RECT 18.560 105.505 18.890 105.835 ;
      RECT 40.640 108.005 41.010 108.375 ;
      RECT 40.685 105.835 40.965 108.005 ;
      RECT 40.660 105.505 40.990 105.835 ;
      RECT 26.640 68.955 27.010 69.325 ;
      RECT 26.660 68.885 26.990 68.955 ;
      RECT 26.685 68.870 26.965 68.885 ;
      RECT 29.660 61.395 29.685 61.725 ;
      RECT 29.685 66.495 29.965 66.510 ;
      RECT 29.660 66.165 29.990 66.495 ;
      RECT 29.685 65.135 29.965 66.165 ;
      RECT 29.660 64.805 29.990 65.135 ;
      RECT 29.965 61.395 29.990 61.725 ;
      RECT 29.685 61.380 29.965 64.805 ;
      RECT 6.985 84.655 7.265 99.020 ;
      RECT 6.960 84.325 7.290 84.655 ;
      RECT 6.985 77.410 7.265 84.325 ;
      RECT 5.440 109.305 5.810 109.675 ;
      RECT 5.460 108.235 5.790 109.305 ;
      RECT 10.240 109.305 10.610 109.675 ;
      RECT 10.260 108.235 10.590 109.305 ;
      RECT 27.540 109.305 27.910 109.675 ;
      RECT 27.560 108.235 27.890 109.305 ;
      RECT 32.340 109.305 32.710 109.675 ;
      RECT 32.360 108.235 32.690 109.305 ;
      RECT 8.785 84.655 9.065 99.020 ;
      RECT 8.760 84.325 9.090 84.655 ;
      RECT 8.785 77.410 9.065 84.325 ;
      RECT 29.085 84.655 29.365 99.020 ;
      RECT 29.060 84.325 29.390 84.655 ;
      RECT 29.085 77.410 29.365 84.325 ;
      RECT 30.885 84.655 31.165 99.020 ;
      RECT 30.860 84.325 31.190 84.655 ;
      RECT 30.885 77.410 31.165 84.325 ;
      RECT 9.960 79.375 9.985 79.705 ;
      RECT 9.985 83.115 10.265 83.130 ;
      RECT 9.960 82.785 10.290 83.115 ;
      RECT 9.985 80.465 10.265 82.785 ;
      RECT 9.940 80.095 10.310 80.465 ;
      RECT 10.265 79.375 10.290 79.705 ;
      RECT 9.985 79.360 10.265 80.095 ;
      RECT 32.060 79.375 32.085 79.705 ;
      RECT 32.085 83.115 32.365 83.130 ;
      RECT 32.060 82.785 32.390 83.115 ;
      RECT 32.085 80.465 32.365 82.785 ;
      RECT 32.040 80.095 32.410 80.465 ;
      RECT 32.365 79.375 32.390 79.705 ;
      RECT 32.085 79.360 32.365 80.095 ;
      RECT 5.485 50.865 5.765 50.880 ;
      RECT 5.460 50.535 5.790 50.865 ;
      RECT 5.485 44.855 5.765 50.535 ;
      RECT 5.460 44.525 5.790 44.855 ;
      RECT 5.485 43.015 5.765 44.525 ;
      RECT 5.440 42.645 5.810 43.015 ;
      RECT 8.485 50.865 8.765 50.880 ;
      RECT 8.460 50.535 8.790 50.865 ;
      RECT 8.485 44.855 8.765 50.535 ;
      RECT 8.460 44.525 8.790 44.855 ;
      RECT 8.485 42.315 8.765 44.525 ;
      RECT 8.440 41.945 8.810 42.315 ;
      RECT 27.585 50.865 27.865 50.880 ;
      RECT 27.560 50.535 27.890 50.865 ;
      RECT 27.585 44.855 27.865 50.535 ;
      RECT 27.560 44.525 27.890 44.855 ;
      RECT 27.585 42.315 27.865 44.525 ;
      RECT 27.540 41.945 27.910 42.315 ;
      RECT 30.585 50.865 30.865 50.880 ;
      RECT 30.560 50.535 30.890 50.865 ;
      RECT 30.585 44.855 30.865 50.535 ;
      RECT 30.560 44.525 30.890 44.855 ;
      RECT 30.585 43.015 30.865 44.525 ;
      RECT 30.540 42.645 30.910 43.015 ;
      RECT 9.685 53.565 9.965 53.580 ;
      RECT 9.660 53.235 9.990 53.565 ;
      RECT 9.685 46.555 9.965 53.235 ;
      RECT 9.660 46.225 9.990 46.555 ;
      RECT 9.685 41.615 9.965 46.225 ;
      RECT 9.640 41.245 10.010 41.615 ;
      RECT 31.785 53.565 32.065 53.580 ;
      RECT 31.760 53.235 32.090 53.565 ;
      RECT 31.785 46.555 32.065 53.235 ;
      RECT 31.760 46.225 32.090 46.555 ;
      RECT 31.785 41.615 32.065 46.225 ;
      RECT 31.740 41.245 32.110 41.615 ;
      RECT 7.285 54.085 7.565 54.100 ;
      RECT 7.260 53.755 7.590 54.085 ;
      RECT 7.285 36.015 7.565 53.755 ;
      RECT 7.240 35.645 7.610 36.015 ;
      RECT 29.385 54.085 29.665 54.100 ;
      RECT 29.360 53.755 29.690 54.085 ;
      RECT 29.385 40.915 29.665 53.755 ;
      RECT 29.340 40.545 29.710 40.915 ;
      RECT 21.985 9.095 22.010 9.425 ;
      RECT 22.010 23.595 22.290 23.610 ;
      RECT 21.985 23.265 22.315 23.595 ;
      RECT 22.010 15.935 22.290 23.265 ;
      RECT 21.985 15.605 22.315 15.935 ;
      RECT 22.290 9.095 22.315 9.425 ;
      RECT 22.010 9.080 22.290 15.605 ;
      RECT 42.815 9.095 42.840 9.425 ;
      RECT 42.840 23.595 43.120 23.610 ;
      RECT 42.815 23.265 43.145 23.595 ;
      RECT 42.840 15.935 43.120 23.265 ;
      RECT 42.815 15.605 43.145 15.935 ;
      RECT 43.120 9.095 43.145 9.425 ;
      RECT 42.840 9.080 43.120 15.605 ;
      RECT 16.585 9.695 16.610 10.025 ;
      RECT 16.610 24.195 16.890 24.210 ;
      RECT 16.585 23.865 16.915 24.195 ;
      RECT 16.610 14.735 16.890 23.865 ;
      RECT 16.585 14.405 16.915 14.735 ;
      RECT 16.890 9.695 16.915 10.025 ;
      RECT 16.610 9.680 16.890 14.405 ;
      RECT 37.415 9.695 37.440 10.025 ;
      RECT 37.440 24.195 37.720 24.210 ;
      RECT 37.415 23.865 37.745 24.195 ;
      RECT 37.440 14.735 37.720 23.865 ;
      RECT 37.415 14.405 37.745 14.735 ;
      RECT 37.720 9.695 37.745 10.025 ;
      RECT 37.440 9.680 37.720 14.405 ;
      RECT 20.210 25.965 20.490 25.980 ;
      RECT 20.185 25.635 20.515 25.965 ;
      RECT 20.210 10.545 20.490 25.635 ;
      RECT 20.185 10.215 20.515 10.545 ;
      RECT 20.210 4.285 20.490 10.215 ;
      RECT 20.165 3.915 20.535 4.285 ;
      RECT 41.040 25.965 41.320 25.980 ;
      RECT 41.015 25.635 41.345 25.965 ;
      RECT 41.040 10.545 41.320 25.635 ;
      RECT 41.015 10.215 41.345 10.545 ;
      RECT 41.040 3.585 41.320 10.215 ;
      RECT 40.995 3.215 41.365 3.585 ;
      RECT 17.785 14.405 17.810 14.735 ;
      RECT 17.810 31.825 18.090 31.840 ;
      RECT 17.785 31.495 18.115 31.825 ;
      RECT 17.810 25.315 18.090 31.495 ;
      RECT 17.785 24.985 18.115 25.315 ;
      RECT 17.810 23.595 18.090 24.985 ;
      RECT 17.785 23.265 18.115 23.595 ;
      RECT 17.810 16.455 18.090 23.265 ;
      RECT 17.785 16.125 18.115 16.455 ;
      RECT 18.090 14.405 18.115 14.735 ;
      RECT 17.810 14.390 18.090 16.125 ;
      RECT 21.385 14.405 21.410 14.735 ;
      RECT 21.410 31.825 21.690 31.840 ;
      RECT 21.385 31.495 21.715 31.825 ;
      RECT 21.410 30.705 21.690 31.495 ;
      RECT 21.385 30.375 21.715 30.705 ;
      RECT 21.410 16.455 21.690 30.375 ;
      RECT 21.385 16.125 21.715 16.455 ;
      RECT 21.690 14.405 21.715 14.735 ;
      RECT 21.410 14.390 21.690 16.125 ;
      RECT 26.185 15.005 26.210 15.335 ;
      RECT 26.210 31.825 26.490 31.840 ;
      RECT 26.185 31.495 26.515 31.825 ;
      RECT 26.210 31.305 26.490 31.495 ;
      RECT 26.185 30.975 26.515 31.305 ;
      RECT 26.210 17.105 26.490 30.975 ;
      RECT 26.185 16.775 26.515 17.105 ;
      RECT 26.490 15.005 26.515 15.335 ;
      RECT 26.210 14.990 26.490 16.775 ;
      RECT 38.615 14.405 38.640 14.735 ;
      RECT 38.640 31.825 38.920 31.840 ;
      RECT 38.615 31.495 38.945 31.825 ;
      RECT 38.640 25.315 38.920 31.495 ;
      RECT 38.615 24.985 38.945 25.315 ;
      RECT 38.640 23.595 38.920 24.985 ;
      RECT 38.615 23.265 38.945 23.595 ;
      RECT 38.640 16.455 38.920 23.265 ;
      RECT 38.615 16.125 38.945 16.455 ;
      RECT 38.920 14.405 38.945 14.735 ;
      RECT 38.640 14.390 38.920 16.125 ;
      RECT 42.215 14.405 42.240 14.735 ;
      RECT 42.240 31.825 42.520 31.840 ;
      RECT 42.215 31.495 42.545 31.825 ;
      RECT 42.240 30.705 42.520 31.495 ;
      RECT 42.215 30.375 42.545 30.705 ;
      RECT 42.240 16.455 42.520 30.375 ;
      RECT 42.215 16.125 42.545 16.455 ;
      RECT 42.520 14.405 42.545 14.735 ;
      RECT 42.240 14.390 42.520 16.125 ;
      RECT 18.385 14.405 18.410 14.735 ;
      RECT 18.410 32.475 18.690 32.490 ;
      RECT 18.385 32.145 18.715 32.475 ;
      RECT 18.410 25.965 18.690 32.145 ;
      RECT 18.385 25.635 18.715 25.965 ;
      RECT 18.410 24.795 18.690 25.635 ;
      RECT 18.385 24.465 18.715 24.795 ;
      RECT 18.410 17.105 18.690 24.465 ;
      RECT 18.385 16.775 18.715 17.105 ;
      RECT 18.690 14.405 18.715 14.735 ;
      RECT 18.410 14.390 18.690 16.775 ;
      RECT 39.215 14.405 39.240 14.735 ;
      RECT 39.240 32.475 39.520 32.490 ;
      RECT 39.215 32.145 39.545 32.475 ;
      RECT 39.240 25.965 39.520 32.145 ;
      RECT 39.215 25.635 39.545 25.965 ;
      RECT 39.240 24.795 39.520 25.635 ;
      RECT 39.215 24.465 39.545 24.795 ;
      RECT 39.240 17.105 39.520 24.465 ;
      RECT 39.215 16.775 39.545 17.105 ;
      RECT 39.520 14.405 39.545 14.735 ;
      RECT 39.240 14.390 39.520 16.775 ;
      RECT 30.000 12.575 30.025 12.905 ;
      RECT 29.980 34.945 30.350 35.315 ;
      RECT 30.305 12.575 30.330 12.905 ;
      RECT 30.025 12.560 30.305 34.945 ;
      RECT 25.585 14.405 25.610 14.735 ;
      RECT 25.565 35.645 25.935 36.015 ;
      RECT 25.610 32.475 25.890 35.645 ;
      RECT 25.585 32.145 25.915 32.475 ;
      RECT 25.610 30.105 25.890 32.145 ;
      RECT 25.585 29.775 25.915 30.105 ;
      RECT 25.610 16.455 25.890 29.775 ;
      RECT 25.585 16.125 25.915 16.455 ;
      RECT 25.890 14.405 25.915 14.735 ;
      RECT 25.610 14.390 25.890 16.125 ;
      RECT 31.200 7.915 31.225 8.245 ;
      RECT 31.180 36.345 31.550 36.715 ;
      RECT 31.505 7.915 31.530 8.245 ;
      RECT 31.225 7.900 31.505 36.345 ;
      RECT 43.415 14.405 43.440 14.735 ;
      RECT 43.395 37.745 43.765 38.115 ;
      RECT 43.440 33.125 43.720 37.745 ;
      RECT 43.415 32.795 43.745 33.125 ;
      RECT 43.440 30.105 43.720 32.795 ;
      RECT 43.415 29.775 43.745 30.105 ;
      RECT 43.440 17.105 43.720 29.775 ;
      RECT 43.415 16.775 43.745 17.105 ;
      RECT 43.720 14.405 43.745 14.735 ;
      RECT 43.440 14.390 43.720 16.775 ;
      RECT 22.585 14.405 22.610 14.735 ;
      RECT 22.565 40.545 22.935 40.915 ;
      RECT 22.610 33.125 22.890 40.545 ;
      RECT 22.585 32.795 22.915 33.125 ;
      RECT 22.610 30.105 22.890 32.795 ;
      RECT 22.585 29.775 22.915 30.105 ;
      RECT 22.610 17.105 22.890 29.775 ;
      RECT 22.585 16.775 22.915 17.105 ;
      RECT 22.890 14.405 22.915 14.735 ;
      RECT 22.610 14.390 22.890 16.775 ;
      RECT 33.000 13.225 33.025 13.555 ;
      RECT 32.980 41.245 33.350 41.615 ;
      RECT 33.305 13.225 33.330 13.555 ;
      RECT 33.025 13.210 33.305 41.245 ;
      RECT 24.985 10.215 25.010 10.545 ;
      RECT 24.965 41.945 25.335 42.315 ;
      RECT 25.290 10.215 25.315 10.545 ;
      RECT 25.010 10.200 25.290 41.945 ;
      RECT 30.600 12.055 30.625 12.385 ;
      RECT 30.580 41.945 30.950 42.315 ;
      RECT 30.625 23.115 30.905 41.945 ;
      RECT 30.600 22.785 30.930 23.115 ;
      RECT 30.625 22.595 30.905 22.785 ;
      RECT 30.600 22.265 30.930 22.595 ;
      RECT 30.905 12.055 30.930 12.385 ;
      RECT 30.625 12.040 30.905 22.265 ;
      RECT 31.800 7.395 31.825 7.725 ;
      RECT 31.825 9.085 32.105 9.100 ;
      RECT 31.800 8.755 32.130 9.085 ;
      RECT 32.105 7.395 32.130 7.725 ;
      RECT 31.825 7.380 32.105 8.755 ;
      RECT 24.385 10.865 24.410 11.195 ;
      RECT 24.365 42.645 24.735 43.015 ;
      RECT 24.690 10.865 24.715 11.195 ;
      RECT 24.410 10.850 24.690 42.645 ;
      RECT 32.400 11.455 32.425 11.785 ;
      RECT 32.380 42.645 32.750 43.015 ;
      RECT 32.425 23.115 32.705 42.645 ;
      RECT 32.400 22.785 32.730 23.115 ;
      RECT 32.425 22.595 32.705 22.785 ;
      RECT 32.400 22.265 32.730 22.595 ;
      RECT 32.705 11.455 32.730 11.785 ;
      RECT 32.425 11.440 32.705 22.265 ;
      RECT 45.215 10.865 45.240 11.195 ;
      RECT 45.195 42.645 45.565 43.015 ;
      RECT 45.520 10.865 45.545 11.195 ;
      RECT 45.240 10.850 45.520 42.645 ;
      RECT 7.885 47.075 8.165 47.090 ;
      RECT 7.860 46.745 8.190 47.075 ;
      RECT 7.885 40.915 8.165 46.745 ;
      RECT 7.840 40.545 8.210 40.915 ;
      RECT 29.985 47.075 30.265 47.090 ;
      RECT 29.960 46.745 30.290 47.075 ;
      RECT 29.985 36.015 30.265 46.745 ;
      RECT 29.940 35.645 30.310 36.015 ;
      RECT 63.015 14.405 63.040 14.735 ;
      RECT 62.995 38.445 63.365 38.815 ;
      RECT 63.040 33.125 63.320 38.445 ;
      RECT 63.015 32.795 63.345 33.125 ;
      RECT 63.040 30.105 63.320 32.795 ;
      RECT 63.015 29.775 63.345 30.105 ;
      RECT 63.040 17.105 63.320 29.775 ;
      RECT 63.015 16.775 63.345 17.105 ;
      RECT 63.320 14.405 63.345 14.735 ;
      RECT 63.040 14.390 63.320 16.775 ;
      RECT 65.415 10.215 65.440 10.545 ;
      RECT 65.395 39.145 65.765 39.515 ;
      RECT 65.720 10.215 65.745 10.545 ;
      RECT 65.440 10.200 65.720 39.145 ;
      RECT 64.815 10.865 64.840 11.195 ;
      RECT 64.795 39.845 65.165 40.215 ;
      RECT 65.120 10.865 65.145 11.195 ;
      RECT 64.840 10.850 65.120 39.845 ;
      RECT 53.215 8.095 53.240 8.425 ;
      RECT 53.240 24.715 53.520 24.730 ;
      RECT 53.215 24.385 53.545 24.715 ;
      RECT 53.240 24.195 53.520 24.385 ;
      RECT 53.215 23.865 53.545 24.195 ;
      RECT 53.240 9.595 53.520 23.865 ;
      RECT 53.215 9.265 53.545 9.595 ;
      RECT 53.520 8.095 53.545 8.425 ;
      RECT 53.240 8.080 53.520 9.265 ;
      RECT 51.415 8.095 51.440 8.425 ;
      RECT 51.440 25.365 51.720 25.380 ;
      RECT 51.415 25.035 51.745 25.365 ;
      RECT 51.440 24.195 51.720 25.035 ;
      RECT 51.415 23.865 51.745 24.195 ;
      RECT 51.440 8.945 51.720 23.865 ;
      RECT 51.415 8.615 51.745 8.945 ;
      RECT 51.720 8.095 51.745 8.425 ;
      RECT 51.440 8.080 51.720 8.615 ;
      RECT 72.940 41.245 73.310 41.615 ;
      RECT 72.985 34.155 73.265 41.245 ;
      RECT 72.940 33.785 73.310 34.155 ;
      RECT 47.015 15.005 47.040 15.335 ;
      RECT 47.040 31.825 47.320 31.840 ;
      RECT 47.015 31.495 47.345 31.825 ;
      RECT 47.040 31.305 47.320 31.495 ;
      RECT 47.015 30.975 47.345 31.305 ;
      RECT 47.040 17.105 47.320 30.975 ;
      RECT 47.015 16.775 47.345 17.105 ;
      RECT 47.320 15.005 47.345 15.335 ;
      RECT 47.040 14.990 47.320 16.775 ;
      RECT 58.215 14.405 58.240 14.735 ;
      RECT 58.240 31.825 58.520 31.840 ;
      RECT 58.215 31.495 58.545 31.825 ;
      RECT 58.240 25.315 58.520 31.495 ;
      RECT 58.215 24.985 58.545 25.315 ;
      RECT 58.240 23.595 58.520 24.985 ;
      RECT 58.215 23.265 58.545 23.595 ;
      RECT 58.240 16.455 58.520 23.265 ;
      RECT 58.215 16.125 58.545 16.455 ;
      RECT 58.520 14.405 58.545 14.735 ;
      RECT 58.240 14.390 58.520 16.125 ;
      RECT 61.815 14.405 61.840 14.735 ;
      RECT 61.840 31.825 62.120 31.840 ;
      RECT 61.815 31.495 62.145 31.825 ;
      RECT 61.840 30.705 62.120 31.495 ;
      RECT 61.815 30.375 62.145 30.705 ;
      RECT 61.840 16.455 62.120 30.375 ;
      RECT 61.815 16.125 62.145 16.455 ;
      RECT 62.120 14.405 62.145 14.735 ;
      RECT 61.840 14.390 62.120 16.125 ;
      RECT 66.615 15.005 66.640 15.335 ;
      RECT 66.640 31.825 66.920 31.840 ;
      RECT 66.615 31.495 66.945 31.825 ;
      RECT 66.640 31.305 66.920 31.495 ;
      RECT 66.615 30.975 66.945 31.305 ;
      RECT 66.640 17.105 66.920 30.975 ;
      RECT 66.615 16.775 66.945 17.105 ;
      RECT 66.920 15.005 66.945 15.335 ;
      RECT 66.640 14.990 66.920 16.775 ;
      RECT 50.240 9.595 50.520 9.610 ;
      RECT 50.215 9.265 50.545 9.595 ;
      RECT 50.240 2.885 50.520 9.265 ;
      RECT 50.195 2.515 50.565 2.885 ;
      RECT 62.415 9.095 62.440 9.425 ;
      RECT 62.440 23.595 62.720 23.610 ;
      RECT 62.415 23.265 62.745 23.595 ;
      RECT 62.440 15.935 62.720 23.265 ;
      RECT 62.415 15.605 62.745 15.935 ;
      RECT 62.720 9.095 62.745 9.425 ;
      RECT 62.440 9.080 62.720 15.605 ;
      RECT 66.015 14.405 66.040 14.735 ;
      RECT 65.995 42.645 66.365 43.015 ;
      RECT 66.040 32.475 66.320 42.645 ;
      RECT 66.015 32.145 66.345 32.475 ;
      RECT 66.040 30.105 66.320 32.145 ;
      RECT 66.015 29.775 66.345 30.105 ;
      RECT 66.040 16.455 66.320 29.775 ;
      RECT 66.015 16.125 66.345 16.455 ;
      RECT 66.320 14.405 66.345 14.735 ;
      RECT 66.040 14.390 66.320 16.125 ;
      RECT 58.815 14.405 58.840 14.735 ;
      RECT 58.840 32.475 59.120 32.490 ;
      RECT 58.815 32.145 59.145 32.475 ;
      RECT 58.840 25.965 59.120 32.145 ;
      RECT 58.815 25.635 59.145 25.965 ;
      RECT 58.840 24.795 59.120 25.635 ;
      RECT 58.815 24.465 59.145 24.795 ;
      RECT 58.840 17.105 59.120 24.465 ;
      RECT 58.815 16.775 59.145 17.105 ;
      RECT 59.120 14.405 59.145 14.735 ;
      RECT 58.840 14.390 59.120 16.775 ;
      RECT 46.415 14.405 46.440 14.735 ;
      RECT 46.440 32.475 46.720 34.630 ;
      RECT 46.415 32.145 46.745 32.475 ;
      RECT 46.440 30.105 46.720 32.145 ;
      RECT 46.415 29.775 46.745 30.105 ;
      RECT 46.440 16.455 46.720 29.775 ;
      RECT 46.415 16.125 46.745 16.455 ;
      RECT 46.720 14.405 46.745 14.735 ;
      RECT 46.440 14.390 46.720 16.125 ;
      RECT 52.085 47.075 52.365 47.090 ;
      RECT 52.060 46.745 52.390 47.075 ;
      RECT 52.085 38.815 52.365 46.745 ;
      RECT 52.040 38.445 52.410 38.815 ;
      RECT 74.185 47.075 74.465 47.090 ;
      RECT 74.160 46.745 74.490 47.075 ;
      RECT 74.185 43.015 74.465 46.745 ;
      RECT 74.140 42.645 74.510 43.015 ;
      RECT 60.640 25.965 60.920 25.980 ;
      RECT 60.615 25.635 60.945 25.965 ;
      RECT 60.640 10.545 60.920 25.635 ;
      RECT 60.615 10.215 60.945 10.545 ;
      RECT 60.640 4.285 60.920 10.215 ;
      RECT 60.595 3.915 60.965 4.285 ;
      RECT 81.845 34.945 82.215 35.315 ;
      RECT 81.890 34.155 82.170 34.945 ;
      RECT 81.845 33.785 82.215 34.155 ;
      RECT 53.840 24.195 54.120 24.210 ;
      RECT 53.815 23.865 54.145 24.195 ;
      RECT 53.840 8.425 54.120 23.865 ;
      RECT 53.815 8.095 54.145 8.425 ;
      RECT 53.840 1.485 54.120 8.095 ;
      RECT 53.795 1.115 54.165 1.485 ;
      RECT 57.015 9.695 57.040 10.025 ;
      RECT 57.040 24.195 57.320 24.210 ;
      RECT 57.015 23.865 57.345 24.195 ;
      RECT 57.040 14.735 57.320 23.865 ;
      RECT 57.015 14.405 57.345 14.735 ;
      RECT 57.320 9.695 57.345 10.025 ;
      RECT 57.040 9.680 57.320 14.405 ;
      RECT 49.685 50.865 49.965 50.880 ;
      RECT 49.660 50.535 49.990 50.865 ;
      RECT 49.685 44.855 49.965 50.535 ;
      RECT 49.660 44.525 49.990 44.855 ;
      RECT 49.685 40.215 49.965 44.525 ;
      RECT 49.640 39.845 50.010 40.215 ;
      RECT 52.685 50.865 52.965 50.880 ;
      RECT 52.660 50.535 52.990 50.865 ;
      RECT 52.685 44.855 52.965 50.535 ;
      RECT 52.660 44.525 52.990 44.855 ;
      RECT 52.685 39.515 52.965 44.525 ;
      RECT 52.640 39.145 53.010 39.515 ;
      RECT 71.785 50.865 72.065 50.880 ;
      RECT 71.760 50.535 72.090 50.865 ;
      RECT 71.785 44.855 72.065 50.535 ;
      RECT 71.760 44.525 72.090 44.855 ;
      RECT 71.785 39.515 72.065 44.525 ;
      RECT 71.740 39.145 72.110 39.515 ;
      RECT 74.785 50.865 75.065 50.880 ;
      RECT 74.760 50.535 75.090 50.865 ;
      RECT 74.785 44.855 75.065 50.535 ;
      RECT 74.760 44.525 75.090 44.855 ;
      RECT 74.785 40.215 75.065 44.525 ;
      RECT 74.740 39.845 75.110 40.215 ;
      RECT 69.805 37.045 70.175 37.415 ;
      RECT 69.850 30.990 70.130 37.045 ;
      RECT 69.805 30.620 70.175 30.990 ;
      RECT 78.710 37.045 79.080 37.415 ;
      RECT 78.755 30.990 79.035 37.045 ;
      RECT 78.710 30.620 79.080 30.990 ;
      RECT 53.885 53.565 54.165 53.580 ;
      RECT 53.860 53.235 54.190 53.565 ;
      RECT 53.885 46.555 54.165 53.235 ;
      RECT 53.860 46.225 54.190 46.555 ;
      RECT 53.885 35.315 54.165 46.225 ;
      RECT 53.840 34.945 54.210 35.315 ;
      RECT 75.985 53.565 76.265 53.580 ;
      RECT 75.960 53.235 76.290 53.565 ;
      RECT 75.985 46.555 76.265 53.235 ;
      RECT 75.960 46.225 76.290 46.555 ;
      RECT 75.985 35.315 76.265 46.225 ;
      RECT 75.940 34.945 76.310 35.315 ;
      RECT 49.640 24.715 49.920 24.730 ;
      RECT 49.615 24.385 49.945 24.715 ;
      RECT 49.640 2.185 49.920 24.385 ;
      RECT 49.595 1.815 49.965 2.185 ;
      RECT 50.815 6.395 50.840 6.725 ;
      RECT 50.795 37.745 51.165 38.115 ;
      RECT 50.840 21.495 51.120 37.745 ;
      RECT 50.815 21.165 51.145 21.495 ;
      RECT 51.120 6.395 51.145 6.725 ;
      RECT 50.840 6.380 51.120 21.165 ;
      RECT 51.485 54.085 51.765 54.100 ;
      RECT 51.460 53.755 51.790 54.085 ;
      RECT 51.485 43.015 51.765 53.755 ;
      RECT 51.440 42.645 51.810 43.015 ;
      RECT 73.585 54.085 73.865 54.100 ;
      RECT 73.560 53.755 73.890 54.085 ;
      RECT 73.585 38.815 73.865 53.755 ;
      RECT 73.540 38.445 73.910 38.815 ;
    LAYER met3 ;
      RECT 1.700 1.130 54.180 1.470 ;
      RECT 1.700 1.830 49.980 2.170 ;
      RECT 1.700 2.530 50.580 2.870 ;
      RECT 1.700 3.230 41.380 3.570 ;
      RECT 1.700 3.930 60.980 4.270 ;
      RECT 69.680 29.105 73.585 32.510 ;
      RECT 78.585 29.105 82.490 32.510 ;
      RECT 72.865 33.710 73.385 34.230 ;
      RECT 81.770 33.710 82.290 34.230 ;
      RECT 1.700 34.960 82.230 35.300 ;
      RECT 7.225 35.660 30.325 36.000 ;
      RECT 3.300 36.360 31.565 36.700 ;
      RECT 2.700 37.060 79.095 37.400 ;
      RECT 1.700 37.760 51.180 38.100 ;
      RECT 1.700 38.460 73.925 38.800 ;
      RECT 1.700 39.160 72.125 39.500 ;
      RECT 1.700 39.860 75.125 40.200 ;
      RECT 1.700 40.560 29.725 40.900 ;
      RECT 1.700 41.260 73.325 41.600 ;
      RECT 1.700 41.960 27.925 42.300 ;
      RECT 30.565 41.960 46.180 42.300 ;
      RECT 1.700 42.660 30.925 43.000 ;
      RECT 32.365 42.660 45.580 43.000 ;
      RECT 51.425 42.660 74.525 43.000 ;
      RECT 6.625 55.770 19.625 56.110 ;
      RECT 28.725 55.770 41.725 56.110 ;
      RECT 50.825 55.770 63.825 56.110 ;
      RECT 72.925 55.770 85.925 56.110 ;
      RECT 4.825 56.470 13.325 56.810 ;
      RECT 26.925 56.470 35.425 56.810 ;
      RECT 49.025 56.470 57.525 56.810 ;
      RECT 71.125 56.470 79.625 56.810 ;
      RECT 4.510 57.680 11.540 66.720 ;
      RECT 26.610 57.680 33.640 66.720 ;
      RECT 48.710 57.680 55.740 66.720 ;
      RECT 70.810 57.680 77.840 66.720 ;
      RECT 9.265 68.120 9.785 68.640 ;
      RECT 31.365 68.120 31.885 68.640 ;
      RECT 53.465 68.120 53.985 68.640 ;
      RECT 75.565 68.120 76.085 68.640 ;
      RECT 1.700 68.970 71.225 69.310 ;
      RECT 1.700 71.840 77.825 72.180 ;
      RECT 9.925 80.110 15.075 80.450 ;
      RECT 32.025 80.110 37.175 80.450 ;
      RECT 54.125 80.110 59.275 80.450 ;
      RECT 76.225 80.110 81.375 80.450 ;
      RECT 5.725 82.210 21.375 82.550 ;
      RECT 27.825 82.210 43.475 82.550 ;
      RECT 49.925 82.210 65.575 82.550 ;
      RECT 72.025 82.210 87.675 82.550 ;
      RECT 20.865 83.750 23.845 86.230 ;
      RECT 42.965 83.750 45.945 86.230 ;
      RECT 65.065 83.750 68.045 86.230 ;
      RECT 87.165 83.750 90.145 86.230 ;
      RECT 23.125 87.430 23.645 87.950 ;
      RECT 45.225 87.430 45.745 87.950 ;
      RECT 67.325 87.430 67.845 87.950 ;
      RECT 89.425 87.430 89.945 87.950 ;
      RECT 1.700 98.570 77.825 98.910 ;
      RECT 1.700 100.910 71.225 101.250 ;
      RECT 10.525 101.910 25.225 102.250 ;
      RECT 32.625 101.910 47.325 102.250 ;
      RECT 54.725 101.910 69.425 102.250 ;
      RECT 76.825 101.910 91.525 102.250 ;
      RECT 1.700 108.020 85.225 108.360 ;
    LAYER met4 ;
      RECT 70.440 29.365 73.325 31.950 ;
      RECT 72.865 32.250 73.385 34.230 ;
      RECT 70.440 31.950 73.385 32.250 ;
      RECT 79.345 29.365 82.230 31.950 ;
      RECT 81.770 32.250 82.290 34.230 ;
      RECT 79.345 31.950 82.290 32.250 ;
      RECT 9.265 66.160 9.785 68.640 ;
      RECT 5.070 58.240 10.980 66.160 ;
      RECT 31.365 66.160 31.885 68.640 ;
      RECT 27.170 58.240 33.080 66.160 ;
      RECT 53.465 66.160 53.985 68.640 ;
      RECT 49.270 58.240 55.180 66.160 ;
      RECT 75.565 66.160 76.085 68.640 ;
      RECT 71.370 58.240 77.280 66.160 ;
      RECT 23.125 84.010 23.585 85.670 ;
      RECT 23.125 85.670 23.645 87.950 ;
      RECT 21.625 84.010 23.125 85.970 ;
      RECT 45.225 84.010 45.685 85.670 ;
      RECT 45.225 85.670 45.745 87.950 ;
      RECT 43.725 84.010 45.225 85.970 ;
      RECT 67.325 84.010 67.785 85.670 ;
      RECT 67.325 85.670 67.845 87.950 ;
      RECT 65.825 84.010 67.325 85.970 ;
      RECT 89.425 84.010 89.885 85.670 ;
      RECT 89.425 85.670 89.945 87.950 ;
      RECT 87.925 84.010 89.425 85.970 ;
      RECT 70.440 29.365 73.385 34.230 ;
      RECT 79.345 29.365 82.290 34.230 ;
      RECT 5.070 58.240 10.980 68.640 ;
      RECT 27.170 58.240 33.080 68.640 ;
      RECT 49.270 58.240 55.180 68.640 ;
      RECT 71.370 58.240 77.280 68.640 ;
      RECT 21.625 84.010 23.645 87.950 ;
      RECT 43.725 84.010 45.745 87.950 ;
      RECT 65.825 84.010 67.845 87.950 ;
      RECT 87.925 84.010 89.945 87.950 ;
  END
END wu

END LIBRARY
